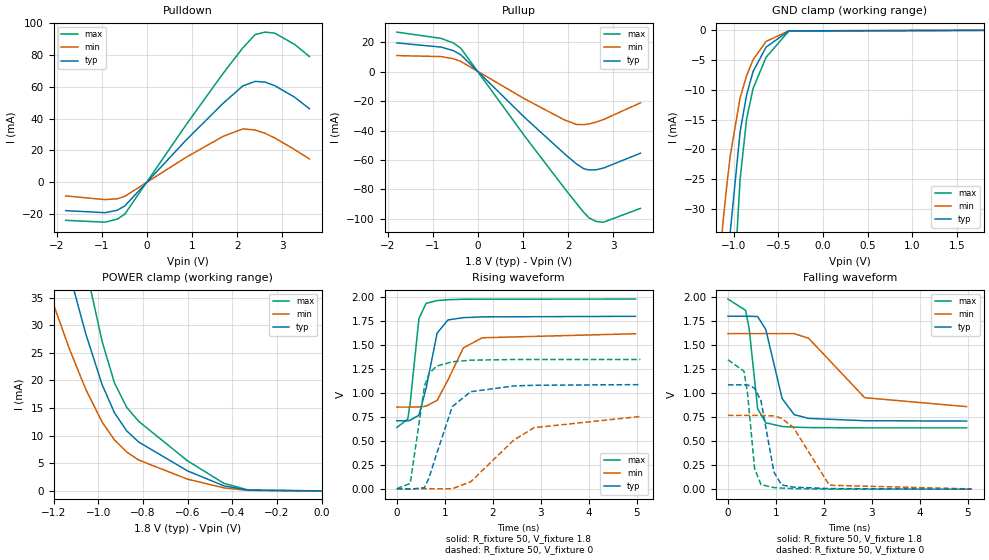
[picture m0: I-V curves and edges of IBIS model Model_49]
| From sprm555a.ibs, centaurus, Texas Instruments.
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| Model based on original model for BC1833DV40DCMLBPBFBP18LL_SSDHH
|   Sub model BC40DCM_H_PUPDOFF_10P_SC1_1P8
[model]   Model_49
|[Description]  [1.8V-I/O-PI-SLOW, IND, 10%]
|   Slow slew rate (SC1 = 1),Weak pull up/down disabled,Industrial
|   temperature range (-40C to 125C, 25C nominal),10% power supply
|   tolerance
|[Input Load]   PI
|[Output Drive] SLOW
|Voltage   1.8V
|Mode   I/O
Model_type   I/O
Polarity   Non-Inverting
Enable   Active-Low
Vinl =  0.63
Vinh =  1.17
Cref =  15pF
Rref =  100.0000M
Vref =  0V
Vmeas =  0.9
C_comp   2.344425p   2.25547p   2.363434p
[Model Spec]
Vinl   0.63   0.567   0.693
Vinh   1.17   1.053   1.287
[Temperature Range]   25   125   -40
[Voltage Range]   1.8   1.62   1.98
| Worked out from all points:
|   slope of the pulldown table from 0 to 0.27 V, typ, clamps not added: 32.2 ohm
|   slope of the pullup table from 0 to 0.27 V, typ, clamps not added: 32.6 ohm
|   GND clamp passes 1 mA (typ) near -0.53 V on its own axis
|   POWER clamp passes 1 mA (typ) near -0.44 V on its own axis
|   rising waveform, R_fixture 50, V_fixture 1.8: 20-80 % time 249ps typ, 424ps min, 162ps max; typ from 0.709 V to 1.8 V
|   rising waveform, R_fixture 50, V_fixture 0: 20-80 % time 430ps typ, 992ps min, 232ps max; typ from 0 V to 1.09 V
|   falling waveform, R_fixture 50, V_fixture 1.8: 20-80 % time 310ps typ, 792ps min, 166ps max; typ from 1.8 V to 0.709 V
|   falling waveform, R_fixture 50, V_fixture 0: 20-80 % time 228ps typ, 465ps min, 151ps max; typ from 1.09 V to 0 V
[POWER_clamp]
-1.8V     158.8mA    112.5mA    219.7mA
-1.255V   59.93mA    40mA       84.85mA
-1.127V   39.08mA    25.51mA    55.74mA
-1.055V   28.36mA    18.34mA    40.4mA
-981.8mV  19.18mA    12.43mA    26.97mA
-927.3mV  14.16mA    9.242mA    19.58mA
-872.7mV  10.89mA    7.052mA    15.14mA
-818.2mV  8.843mA    5.581mA    12.58mA
-600mV    3.63mA     2.129mA    5.448mA
-436.4mV  903.9uA    539.1uA    1.358mA
-327.3mV  138.2uA    94.86uA    160.4uA
0V        19.3nA     120.3nA    352.8nA
[Pulldown]
-1.8V     -17.92mA   -8.674mA   -24.03mA
-927.3mV  -19.22mA   -10.99mA   -25.2mA
-654.5mV  -17.65mA   -10.46mA   -23.22mA
-490.9mV  -14.97mA   -8.904mA   -20.12mA
872.7mV   26.63mA    15.72mA    36.29mA
1.691V    49.7mA     28.87mA    68.59mA
2.127V    60.63mA    33.53mA    84.59mA
2.4V      63.43mA    32.84mA    92.9mA
2.618V    62.99mA    30.74mA    94.47mA
2.836V    60.69mA    27.76mA    93.76mA
3.273V    53.49mA    20.53mA    86.73mA
3.6V      46.26mA    14.64mA    79.12mA
[Pullup]
-1.8V     19.42mA    10.82mA    26.76mA
-818.2mV  16.58mA    10.15mA    22.47mA
-545.5mV  14.19mA    8.648mA    19.37mA
-381.8mV  11.34mA    6.842mA    15.75mA
1.036V    -31.26mA   -18.6mA    -43.9mA
1.909V    -55.59mA   -32.73mA   -78.89mA
2.182V    -62.72mA   -35.92mA   -89.47mA
2.345V    -65.94mA   -36.05mA   -95.62mA
2.455V    -66.75mA   -35.58mA   -99.18mA
2.618V    -66.67mA   -34.29mA   -101.7mA
2.782V    -65.46mA   -32.56mA   -102.2mA
3.6V      -55.4mA    -21.22mA   -92.82mA
[GND_clamp]
-1.8V     -270.2mA   -170.2mA   -430.1mA
-1.255V   -91.66mA   -55.91mA   -148.4mA
-1.145V   -59.91mA   -36.44mA   -97.09mA
-1.109V   -50.48mA   -30.83mA   -81.55mA
-1.073V   -41.73mA   -25.65mA   -67.05mA
-1.036V   -33.66mA   -20.92mA   -53.59mA
-927.3mV  -17.07mA   -11.35mA   -25.04mA
-854.5mV  -10.86mA   -7.616mA   -14.91mA
-781.8mV  -6.919mA   -4.945mA   -9.771mA
-636.4mV  -2.823mA   -1.868mA   -4.529mA
-381.8mV  -84.73uA   -78.7uA    -126.1uA
1.8V      19.3nA     3.129uA    310.3nA
[Ramp]
dV/dt_f 0.66158729/0.31312099n 0.46775844/0.81509621n  0.8109244/0.168039n
dV/dt_r 0.65950887/0.43320351n 0.47445953/1.0525249n 0.81582639/0.23270059n
R_load = 50
[Rising Waveform]
R_fixture = 50
V_fixture = 1.8
V_fixture_min = 1.62
V_fixture_max = 1.98
0s        709.2mV    852.1mV    638.7mV
228.5ps   709.2mV    852.1mV    727.2mV
279ps     715mV      852.1mV    897.2mV
460.7ps   767.4mV    852.4mV    1.775V
609.6ps   1.047V     863.3mV    1.935V
840.4ps   1.625V     922.2mV    1.965V
1.066ns   1.762V     1.136V     1.973V
1.387ns   1.786V     1.471V     1.978V
1.781ns   1.794V     1.576V     1.979V
4.974ns   1.8V       1.618V     1.98V
[Rising Waveform]
R_fixture = 50
V_fixture = 0
V_fixture_min = 0
V_fixture_max = 0
0s        0V         0V         0V
279.1ps   -4.496mV   0V         55.36mV
575.6ps   11.17mV    0V         1.07V
671.5ps   114.3mV    0V         1.203V
828.7ps   363mV      0V         1.28V
1.155ns   856.5mV    0V         1.325V
1.537ns   1.013V     71.46mV    1.342V
2.437ns   1.073V     507.6mV    1.349V
2.86ns    1.08V      637.5mV    1.349V
5.077ns   1.087V     754.7mV    1.349V
[Falling Waveform]
R_fixture = 50
V_fixture = 1.8
V_fixture_min = 1.62
V_fixture_max = 1.98
0s        1.801V     1.62V      1.98V
369.4ps   1.801V     1.62V      1.862V
442.6ps   1.801V     1.62V      1.671V
619.8ps   1.798V     1.62V      837.6mV
788.4ps   1.664V     1.62V      691.6mV
1.13ns    943.7mV    1.62V      652.7mV
1.38ns    776mV      1.62V      645.7mV
1.681ns   737.2mV    1.572V     641.7mV
2.85ns    712.9mV    952.7mV    638.2mV
4.974ns   709mV      859.7mV    637.9mV
[Falling Waveform]
R_fixture = 50
V_fixture = 0
V_fixture_min = 0
V_fixture_max = 0
0s        1.086V     768.6mV    1.348V
334.1ps   1.086V     768.6mV    1.229V
410.6ps   1.086V     768.6mV    991.6mV
554.9ps   1.052V     768.6mV    217.6mV
688.5ps   921.5mV    768.6mV    47.07mV
958.6ps   178.4mV    762.8mV    16.84mV
1.117ns   44.46mV    738.1mV    11.67mV
1.36ns    21.32mV    645.9mV    5.206mV
2.114ns   6.036mV    40.95mV    0V
5.077ns   0V         2.212mV    0V
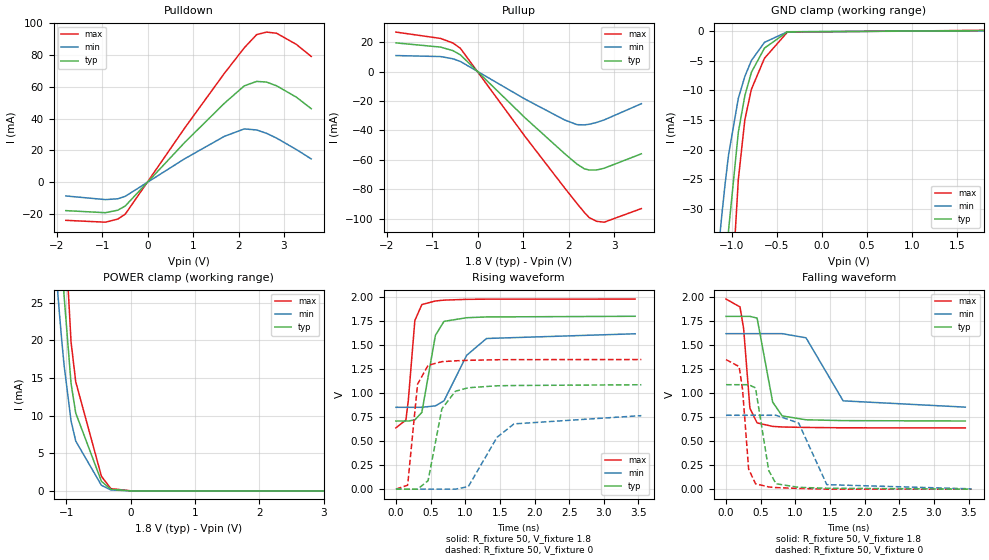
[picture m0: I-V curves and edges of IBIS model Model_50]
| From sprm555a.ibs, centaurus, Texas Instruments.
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| Model based on original model for BC1833DV40DCMLBPBFBP18LL_SSDHH
|   Sub model BC40DCM_H_PD_ON_10P_!SC1_1P8
[model]   Model_50
|[Description]  [1.8V-I/O-PD-FAST, IND, 10%]
|   Fast slew rate (SC1 = 0),Weak internal pull-down,Industrial
|   temperature range (-40C to 125C, 25C nominal),10% power supply
|   tolerance
|[Input Load]   PD
|[Output Drive] FAST
|Voltage   1.8V
|Mode   I/O
Model_type   I/O
Polarity   Non-Inverting
Enable   Active-Low
Vinl =  0.63
Vinh =  1.17
Cref =  15pF
Rref =  100.0000M
Vref =  0V
Vmeas =  0.9
C_comp   2.344425p   2.25547p   2.363434p
[Model Spec]
Vinl   0.63   0.567   0.693
Vinh   1.17   1.053   1.287
[Temperature Range]   25   125   -40
[Voltage Range]   1.8   1.62   1.98
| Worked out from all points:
|   slope of the pulldown table from 0 to 0.27 V, typ, clamps not added: 32.2 ohm
|   slope of the pullup table from 0 to 0.27 V, typ, clamps not added: 32.5 ohm
|   GND clamp passes 1 mA (typ) near -0.53 V on its own axis
|   POWER clamp passes 1 mA (typ) near -0.43 V on its own axis
|   rising waveform, R_fixture 50, V_fixture 1.8: 20-80 % time 145ps typ, 331ps min, 88.8ps max; typ from 0.708 V to 1.8 V
|   rising waveform, R_fixture 50, V_fixture 0: 20-80 % time 176ps typ, 381ps min, 101ps max; typ from 0 V to 1.09 V
|   falling waveform, R_fixture 50, V_fixture 1.8: 20-80 % time 130ps typ, 293ps min, 86ps max; typ from 1.8 V to 0.709 V
|   falling waveform, R_fixture 50, V_fixture 0: 20-80 % time 113ps typ, 213ps min, 82.8ps max; typ from 1.09 V to 0 V
[POWER_clamp]
-1.8V     158.9mA    112.6mA    219.9mA
-1.255V   60.04mA    40.04mA    85.04mA
-1.145V   41.99mA    27.45mA    59.9mA
-1.109V   36.4mA     23.66mA    51.96mA
-1.073V   31.03mA    20.08mA    44.3mA
-1.036V   25.91mA    16.71mA    36.9mA
-927.3mV  14.27mA    9.297mA    19.77mA
-854.5mV  10.33mA    6.619mA    14.49mA
-454.5mV  1.273mA    741.7uA    1.94mA
-309.1mV  221.6uA    132.8uA    307.9uA
18.18mV   0A         0A         0A
3.6V      0A         0A         0A
[Pulldown]
-1.8V     -17.92mA   -8.674mA   -24.03mA
-927.3mV  -19.22mA   -10.99mA   -25.2mA
-654.5mV  -17.65mA   -10.46mA   -23.22mA
-490.9mV  -14.97mA   -8.904mA   -20.12mA
818.2mV   25.05mA    14.78mA    34.16mA
1.691V    49.7mA     28.87mA    68.58mA
2.127V    60.63mA    33.53mA    84.59mA
2.4V      63.43mA    32.85mA    92.9mA
2.618V    62.99mA    30.74mA    94.47mA
2.836V    60.69mA    27.76mA    93.76mA
3.273V    53.49mA    20.53mA    86.73mA
3.6V      46.26mA    14.64mA    79.12mA
[Pullup]
-1.8V     19.47mA    10.86mA    26.81mA
-818.2mV  16.61mA    10.18mA    22.5mA
-545.5mV  14.2mA     8.665mA    19.39mA
-381.8mV  11.35mA    6.855mA    15.77mA
1.036V    -31.31mA   -18.66mA   -43.94mA
1.909V    -55.72mA   -32.86mA   -78.99mA
2.182V    -62.87mA   -36.1mA    -89.59mA
2.345V    -66.12mA   -36.26mA   -95.76mA
2.455V    -66.95mA   -35.82mA   -99.33mA
2.618V    -66.9mA    -34.58mA   -101.8mA
2.782V    -65.72mA   -32.89mA   -102.4mA
3.6V      -55.92mA   -21.86mA   -93.15mA
[GND_clamp]
-1.8V     -270.2mA   -170.2mA   -430.1mA
-1.255V   -91.66mA   -55.91mA   -148.4mA
-1.145V   -59.91mA   -36.45mA   -97.1mA
-1.109V   -50.48mA   -30.83mA   -81.56mA
-1.073V   -41.73mA   -25.65mA   -67.06mA
-1.036V   -33.67mA   -20.93mA   -53.6mA
-927.3mV  -17.08mA   -11.35mA   -25.06mA
-854.5mV  -10.88mA   -7.623mA   -14.95mA
-781.8mV  -6.944mA   -4.955mA   -9.81mA
-636.4mV  -2.852mA   -1.883mA   -4.568mA
-381.8mV  -107.5uA   -91.83uA   -158.4uA
1.8V      101.9uA    59.86uA    152.6uA
[Ramp]
dV/dt_f 0.66466633/0.13254164n 0.47017584/0.29934086n 0.81362785/87.565615p
dV/dt_r   0.663957/0.17824598n  0.4809099/0.3977937n  0.8179783/0.10140493n
R_load = 50
[Rising Waveform]
R_fixture = 50
V_fixture = 1.8
V_fixture_min = 1.62
V_fixture_max = 1.98
0s        708.5mV    851.3mV    637.7mV
143.7ps   708.5mV    851.3mV    718.9mV
178.5ps   708.5mV    851.3mV    921.1mV
273.2ps   720.3mV    851.3mV    1.754V
374.1ps   798mV      851.3mV    1.92V
569.9ps   1.6V       866.3mV    1.957V
694.1ps   1.745V     919.3mV    1.966V
1.021ns   1.783V     1.392V     1.974V
1.307ns   1.791V     1.567V     1.976V
3.453ns   1.798V     1.616V     1.977V
[Rising Waveform]
R_fixture = 50
V_fixture = 0
V_fixture_min = 0
V_fixture_max = 0
0s        0V         0V         0V
168.9ps   0V         0V         40.84mV
312.3ps   0V         0V         1.092V
464.1ps   88.01mV    0V         1.288V
663.2ps   835.8mV    0V         1.326V
857.8ps   1.018V     0V         1.335V
1.045ns   1.055V     26.66mV    1.34V
1.459ns   1.075V     539.2mV    1.346V
1.704ns   1.078V     679mV      1.347V
3.542ns   1.086V     764.7mV    1.348V
[Falling Waveform]
R_fixture = 50
V_fixture = 1.8
V_fixture_min = 1.62
V_fixture_max = 1.98
0s        1.798V     1.618V     1.978V
201.6ps   1.798V     1.618V     1.896V
253.7ps   1.798V     1.618V     1.671V
344.4ps   1.798V     1.618V     841.4mV
448.2ps   1.78V      1.618V     689.6mV
672.7ps   906.5mV    1.618V     653mV
809.7ps   762.1mV    1.618V     647.1mV
1.154ns   721.9mV    1.575V     642.3mV
1.69ns    713.1mV    918.9mV    638.4mV
3.453ns   709.3mV    853.5mV    637.1mV
[Falling Waveform]
R_fixture = 50
V_fixture = 0
V_fixture_min = 0
V_fixture_max = 0
0s        1.087V     768.9mV    1.348V
189.2ps   1.087V     768.9mV    1.275V
238.1ps   1.087V     768.9mV    1.038V
325.8ps   1.087V     768.9mV    209.8mV
425.1ps   1.054V     768.9mV    56.16mV
615.9ps   194.4mV    768.9mV    22.91mV
720.9ps   56.52mV    768.9mV    16.38mV
1.048ns   18.77mV    687.9mV    7.302mV
1.454ns   9.815mV    46.84mV    0V
3.542ns   0V         3.333mV    0V
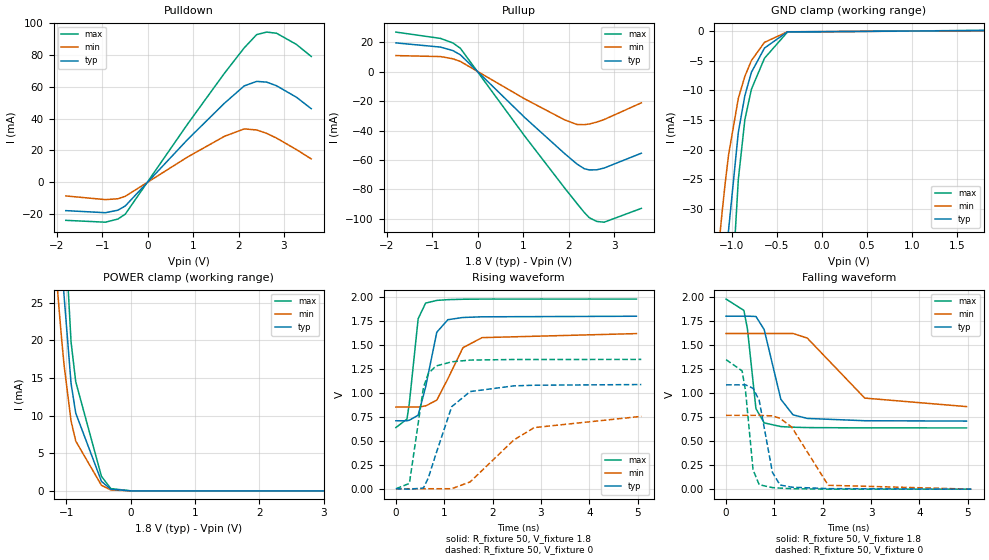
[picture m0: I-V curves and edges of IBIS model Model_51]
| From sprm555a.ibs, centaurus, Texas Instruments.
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| Model based on original model for BC1833DV40DCMLBPBFBP18LL_SSDHH
|   Sub model BC40DCM_H_PD_ON_10P_SC1_1P8
[model]   Model_51
|[Description]  [1.8V-I/O-PD-SLOW, IND, 10%]
|   Slow slew rate (SC1 = 1),Weak internal pull-down,Industrial
|   temperature range (-40C to 125C, 25C nominal),10% power supply
|   tolerance
|[Input Load]   PD
|[Output Drive] SLOW
|Voltage   1.8V
|Mode   I/O
Model_type   I/O
Polarity   Non-Inverting
Enable   Active-Low
Vinl =  0.63
Vinh =  1.17
Cref =  15pF
Rref =  100.0000M
Vref =  0V
Vmeas =  0.9
C_comp   2.344425p   2.25547p   2.363434p
[Model Spec]
Vinl   0.63   0.567   0.693
Vinh   1.17   1.053   1.287
[Temperature Range]   25   125   -40
[Voltage Range]   1.8   1.62   1.98
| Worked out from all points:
|   slope of the pulldown table from 0 to 0.27 V, typ, clamps not added: 32.2 ohm
|   slope of the pullup table from 0 to 0.27 V, typ, clamps not added: 32.6 ohm
|   GND clamp passes 1 mA (typ) near -0.53 V on its own axis
|   POWER clamp passes 1 mA (typ) near -0.43 V on its own axis
|   rising waveform, R_fixture 50, V_fixture 1.8: 20-80 % time 249ps typ, 424ps min, 162ps max; typ from 0.708 V to 1.8 V
|   rising waveform, R_fixture 50, V_fixture 0: 20-80 % time 429ps typ, 992ps min, 231ps max; typ from 0 V to 1.09 V
|   falling waveform, R_fixture 50, V_fixture 1.8: 20-80 % time 310ps typ, 792ps min, 166ps max; typ from 1.8 V to 0.708 V
|   falling waveform, R_fixture 50, V_fixture 0: 20-80 % time 227ps typ, 466ps min, 151ps max; typ from 1.08 V to 0 V
[POWER_clamp]
-1.8V     158.9mA    112.6mA    219.9mA
-1.255V   60.04mA    40.04mA    85.04mA
-1.145V   41.99mA    27.45mA    59.9mA
-1.109V   36.4mA     23.66mA    51.96mA
-1.073V   31.03mA    20.08mA    44.3mA
-1.036V   25.91mA    16.71mA    36.9mA
-927.3mV  14.27mA    9.297mA    19.77mA
-854.5mV  10.33mA    6.619mA    14.49mA
-454.5mV  1.273mA    741.7uA    1.94mA
-309.1mV  221.6uA    132.8uA    307.9uA
18.18mV   0A         0A         0A
3.6V      0A         0A         0A
[Pulldown]
-1.8V     -17.92mA   -8.674mA   -24.03mA
-927.3mV  -19.22mA   -10.99mA   -25.2mA
-654.5mV  -17.65mA   -10.46mA   -23.22mA
-490.9mV  -14.97mA   -8.904mA   -20.12mA
872.7mV   26.63mA    15.72mA    36.29mA
1.691V    49.7mA     28.87mA    68.58mA
2.127V    60.63mA    33.53mA    84.59mA
2.4V      63.43mA    32.85mA    92.9mA
2.618V    62.99mA    30.74mA    94.47mA
2.836V    60.69mA    27.76mA    93.76mA
3.273V    53.49mA    20.53mA    86.73mA
3.6V      46.26mA    14.64mA    79.12mA
[Pullup]
-1.8V     19.42mA    10.82mA    26.76mA
-818.2mV  16.58mA    10.15mA    22.47mA
-545.5mV  14.19mA    8.648mA    19.37mA
-381.8mV  11.34mA    6.842mA    15.75mA
1.036V    -31.26mA   -18.6mA    -43.9mA
1.909V    -55.59mA   -32.73mA   -78.89mA
2.182V    -62.71mA   -35.92mA   -89.46mA
2.345V    -65.94mA   -36.05mA   -95.62mA
2.455V    -66.75mA   -35.58mA   -99.18mA
2.618V    -66.67mA   -34.29mA   -101.7mA
2.782V    -65.46mA   -32.56mA   -102.2mA
3.6V      -55.4mA    -21.22mA   -92.82mA
[GND_clamp]
-1.8V     -270.2mA   -170.2mA   -430.1mA
-1.255V   -91.66mA   -55.91mA   -148.4mA
-1.145V   -59.91mA   -36.45mA   -97.1mA
-1.109V   -50.48mA   -30.83mA   -81.56mA
-1.073V   -41.73mA   -25.65mA   -67.06mA
-1.036V   -33.67mA   -20.93mA   -53.6mA
-927.3mV  -17.08mA   -11.35mA   -25.06mA
-854.5mV  -10.88mA   -7.623mA   -14.95mA
-781.8mV  -6.944mA   -4.955mA   -9.81mA
-636.4mV  -2.852mA   -1.883mA   -4.568mA
-381.8mV  -107.5uA   -91.83uA   -158.4uA
1.8V      101.9uA    59.86uA    152.6uA
[Ramp]
dV/dt_f 0.66084939/0.31244976n 0.46735303/0.81433888n  0.8098709/0.16773637n
dV/dt_r 0.65873585/0.43257283n 0.47403165/1.0514155n 0.81471047/0.23229215n
R_load = 50
[Rising Waveform]
R_fixture = 50
V_fixture = 1.8
V_fixture_min = 1.62
V_fixture_max = 1.98
0s        708.4mV    851.3mV    637.9mV
227.9ps   708.4mV    851.3mV    726mV
275.2ps   713.7mV    851.3mV    881.4mV
460.1ps   766.4mV    851.6mV    1.773V
614.7ps   1.062V     863.3mV    1.935V
845.1ps   1.631V     923.8mV    1.963V
1.074ns   1.762V     1.146V     1.971V
1.386ns   1.785V     1.47V      1.975V
1.781ns   1.792V     1.575V     1.977V
4.974ns   1.798V     1.617V     1.977V
[Rising Waveform]
R_fixture = 50
V_fixture = 0
V_fixture_min = 0
V_fixture_max = 0
0s        0V         0V         0V
278.5ps   -4.495mV   0V         55.36mV
569.3ps   7.749mV    0V         1.057V
671ps     114.4mV    0V         1.203V
828.2ps   363.1mV    0V         1.279V
1.154ns   855.4mV    0V         1.323V
1.536ns   1.013V     71.36mV    1.341V
2.436ns   1.072V     507.4mV    1.347V
2.86ns    1.079V     637.3mV    1.347V
5.076ns   1.086V     754.3mV    1.348V
[Falling Waveform]
R_fixture = 50
V_fixture = 1.8
V_fixture_min = 1.62
V_fixture_max = 1.98
0s        1.799V     1.619V     1.977V
368.9ps   1.799V     1.619V     1.859V
442.2ps   1.799V     1.619V     1.667V
618ps     1.796V     1.619V     837.7mV
788.4ps   1.66V      1.619V     689.3mV
1.133ns   934.9mV    1.619V     651.1mV
1.385ns   773mV      1.619V     644.3mV
1.68ns    735.7mV    1.571V     640.5mV
2.868ns   711.7mV    947.2mV    637.2mV
4.974ns   708.1mV    858.7mV    637mV
[Falling Waveform]
R_fixture = 50
V_fixture = 0
V_fixture_min = 0
V_fixture_max = 0
0s        1.085V     767.8mV    1.347V
332.1ps   1.085V     767.8mV    1.23V
404.3ps   1.085V     767.8mV    1.016V
558.5ps   1.049V     767.8mV    201.7mV
685.2ps   924.8mV    767.8mV    46.5mV
959.4ps   174mV      761.9mV    15.99mV
1.117ns   43.41mV    737.3mV    11.07mV
1.359ns   20.58mV    645mV      4.808mV
2.113ns   5.595mV    40.31mV    0V
5.076ns   0V         0V         0V
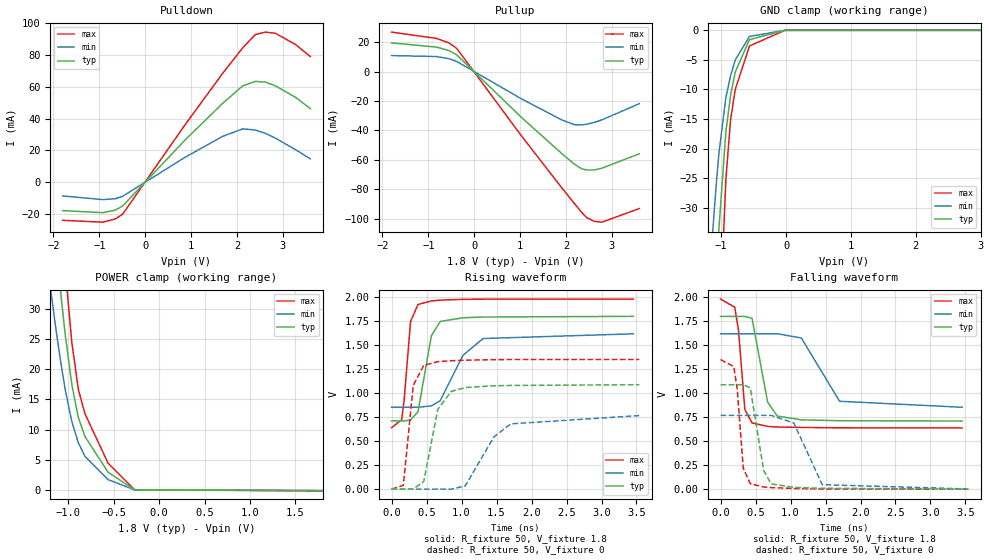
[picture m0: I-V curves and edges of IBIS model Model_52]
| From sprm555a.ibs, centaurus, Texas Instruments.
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| Model based on original model for BC1833DV40DCMLBPBFBP18LL_SSDHH
|   Sub model BC40DCM_H_PU_ON_10P_!SC1_1P8
[model]   Model_52
|[Description]  [1.8V-I/O-PU-FAST, IND, 10%]
|   Fast slew rate (SC1 = 0),Weak internal pull-up,Industrial
|   temperature range (-40C to 125C, 25C nominal),10% power supply
|   tolerance
|[Input Load]   PU
|[Output Drive] FAST
|Voltage   1.8V
|Mode   I/O
Model_type   I/O
Polarity   Non-Inverting
Enable   Active-Low
Vinl =  0.63
Vinh =  1.17
Cref =  15pF
Rref =  100.0000M
Vref =  0V
Vmeas =  0.9
C_comp   2.344425p   2.25547p   2.363434p
[Model Spec]
Vinl   0.63   0.567   0.693
Vinh   1.17   1.053   1.287
[Temperature Range]   25   125   -40
[Voltage Range]   1.8   1.62   1.98
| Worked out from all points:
|   slope of the pulldown table from 0 to 0.27 V, typ, clamps not added: 32.2 ohm
|   slope of the pullup table from 0 to 0.27 V, typ, clamps not added: 32.5 ohm
|   GND clamp passes 1 mA (typ) near -0.52 V on its own axis
|   POWER clamp passes 1 mA (typ) near -0.44 V on its own axis
|   rising waveform, R_fixture 50, V_fixture 1.8: 20-80 % time 145ps typ, 330ps min, 88.8ps max; typ from 0.711 V to 1.8 V
|   rising waveform, R_fixture 50, V_fixture 0: 20-80 % time 176ps typ, 382ps min, 101ps max; typ from 0.002 V to 1.09 V
|   falling waveform, R_fixture 50, V_fixture 1.8: 20-80 % time 130ps typ, 293ps min, 86ps max; typ from 1.8 V to 0.711 V
|   falling waveform, R_fixture 50, V_fixture 0: 20-80 % time 113ps typ, 213ps min, 82.8ps max; typ from 1.09 V to 0.002 V
[POWER_clamp]
-1.8V     158.8mA    112.5mA    219.8mA
-1.255V   59.97mA    40.01mA    84.9mA
-1.145V   41.92mA    27.42mA    59.75mA
-1.109V   36.32mA    23.63mA    51.82mA
-1.073V   30.96mA    20.05mA    44.15mA
-1.036V   25.83mA    16.67mA    36.75mA
-963.6mV  17.54mA    11.39mA    24.55mA
-890.9mV  12.01mA    7.801mA    16.66mA
-818.2mV  8.875mA    5.6mA      12.63mA
-563.6mV  2.954mA    1.727mA    4.458mA
-272.7mV  55.97uA    39.41uA    57.82uA
1.8V      -99.94uA   -59.68uA   -146.8uA
[Pulldown]
-1.8V     -17.92mA   -8.674mA   -24.03mA
-927.3mV  -19.22mA   -10.99mA   -25.21mA
-654.5mV  -17.65mA   -10.46mA   -23.22mA
-490.9mV  -14.97mA   -8.904mA   -20.12mA
872.7mV   26.63mA    15.72mA    36.29mA
1.691V    49.7mA     28.87mA    68.59mA
2.127V    60.63mA    33.53mA    84.59mA
2.4V      63.43mA    32.84mA    92.9mA
2.618V    62.99mA    30.74mA    94.47mA
2.836V    60.69mA    27.76mA    93.76mA
3.273V    53.49mA    20.53mA    86.73mA
3.6V      46.26mA    14.64mA    79.11mA
[Pullup]
-1.8V     19.47mA    10.86mA    26.81mA
-818.2mV  16.61mA    10.18mA    22.5mA
-545.5mV  14.21mA    8.665mA    19.39mA
-381.8mV  11.35mA    6.855mA    15.77mA
1.036V    -31.31mA   -18.66mA   -43.94mA
1.909V    -55.72mA   -32.86mA   -78.99mA
2.182V    -62.87mA   -36.1mA    -89.59mA
2.345V    -66.12mA   -36.26mA   -95.76mA
2.455V    -66.95mA   -35.82mA   -99.33mA
2.618V    -66.9mA    -34.58mA   -101.8mA
2.782V    -65.73mA   -32.89mA   -102.4mA
3.6V      -55.92mA   -21.86mA   -93.15mA
[GND_clamp]
-1.8V     -270.2mA   -170.2mA   -430.1mA
-1.255V   -91.68mA   -55.92mA   -148.5mA
-1.145V   -59.94mA   -36.46mA   -97.15mA
-1.109V   -50.51mA   -30.84mA   -81.62mA
-1.073V   -41.77mA   -25.67mA   -67.14mA
-1.036V   -33.71mA   -20.94mA   -53.69mA
-927.3mV  -17.15mA   -11.38mA   -25.2mA
-854.5mV  -10.96mA   -7.657mA   -15.09mA
-781.8mV  -7.031mA   -4.995mA   -9.958mA
-563.6mV  -1.569mA   -1.036mA   -2.651mA
-18.18mV  0A         0A         0A
3.6V      0A         0A         0A
[Ramp]
dV/dt_f 0.66463764/0.13263058n 0.47013209/0.29941611n 0.81359696/87.584176p
dV/dt_r 0.66384338/0.17819323n  0.4805998/0.39765783n  0.8179891/0.10135865n
R_load = 50
[Rising Waveform]
R_fixture = 50
V_fixture = 1.8
V_fixture_min = 1.62
V_fixture_max = 1.98
0s        710.6mV    852.8mV    640.5mV
143.7ps   710.6mV    852.8mV    722.2mV
178.5ps   710.6mV    852.8mV    925mV
270.8ps   721.7mV    852.8mV    1.745V
377.3ps   806.8mV    852.8mV    1.924V
567.9ps   1.597V     867.4mV    1.96V
694.7ps   1.747V     921.4mV    1.969V
1.021ns   1.785V     1.395V     1.977V
1.307ns   1.793V     1.569V     1.979V
3.453ns   1.8V       1.618V     1.98V
[Rising Waveform]
R_fixture = 50
V_fixture = 0
V_fixture_min = 0
V_fixture_max = 0
0s        2.403mV    0V         0V
167.8ps   2.403mV    0V         40.79mV
309.1ps   2.403mV    0V         1.082V
459.2ps   77.71mV    0V         1.289V
660.4ps   831.9mV    0V         1.328V
851.7ps   1.018V     0V         1.338V
1.053ns   1.058V     34.68mV    1.343V
1.461ns   1.077V     543.1mV    1.349V
1.702ns   1.08V      680.1mV    1.35V
3.54ns    1.088V     766.2mV    1.351V
[Falling Waveform]
R_fixture = 50
V_fixture = 1.8
V_fixture_min = 1.62
V_fixture_max = 1.98
0s        1.8V       1.62V      1.981V
202.5ps   1.8V       1.62V      1.896V
255.7ps   1.8V       1.62V      1.659V
347ps     1.8V       1.62V      831.6mV
449.8ps   1.78V      1.62V      691.6mV
673.3ps   907.4mV    1.62V      655.6mV
810.6ps   763.8mV    1.62V      649.7mV
1.154ns   723.8mV    1.576V     644.9mV
1.701ns   715.1mV    917.3mV    641mV
3.453ns   711.4mV    854.9mV    639.8mV
[Falling Waveform]
R_fixture = 50
V_fixture = 0
V_fixture_min = 0
V_fixture_max = 0
0s        1.089V     770.8mV    1.351V
189.2ps   1.089V     770.8mV    1.278V
238.1ps   1.089V     770.8mV    1.041V
324.3ps   1.089V     770.8mV    220mV
425.1ps   1.056V     770.8mV    58.76mV
616.3ps   195.4mV    770.8mV    25.42mV
722.1ps   58.16mV    770.8mV    18.85mV
1.048ns   20.72mV    689.9mV    9.786mV
1.453ns   11.74mV    49.09mV    4.325mV
3.54ns    2.495mV    4.926mV    2.572mV
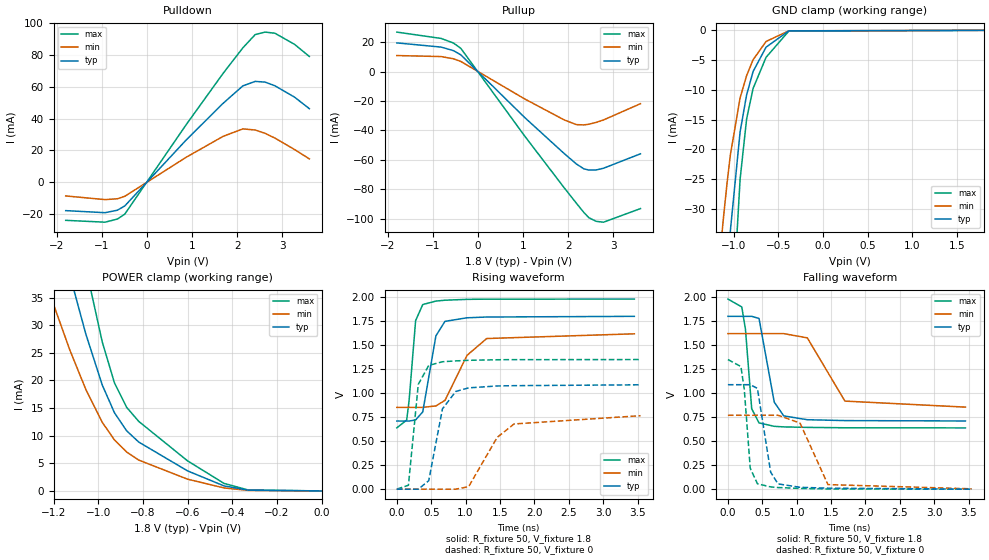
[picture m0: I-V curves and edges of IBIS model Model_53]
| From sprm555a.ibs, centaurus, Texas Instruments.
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| Model based on original model for BC1833DV40DCMLBPBFBP18LL_SSDHH
|   Sub model BC40DCM_H_PUPDOFF_10P_!SC1_1P8
[model]   Model_53
|[Description]  [1.8V-I/O-PI-FAST, IND, 10%]
|   Fast slew rate (SC1 = 0),Weak pull up/down disabled,Industrial
|   temperature range (-40C to 125C, 25C nominal),10% power supply
|   tolerance
|[Input Load]   PI
|[Output Drive] FAST
|Voltage   1.8V
|Mode   I/O
Model_type   I/O
Polarity   Non-Inverting
Enable   Active-Low
Vinl =  0.63
Vinh =  1.17
Cref =  15pF
Rref =  100.0000M
Vref =  0V
Vmeas =  0.9
C_comp   2.344425p   2.25547p   2.363434p
[Model Spec]
Vinl   0.63   0.567   0.693
Vinh   1.17   1.053   1.287
[Temperature Range]   25   125   -40
[Voltage Range]   1.8   1.62   1.98
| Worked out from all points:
|   slope of the pulldown table from 0 to 0.27 V, typ, clamps not added: 32.2 ohm
|   slope of the pullup table from 0 to 0.27 V, typ, clamps not added: 32.5 ohm
|   GND clamp passes 1 mA (typ) near -0.53 V on its own axis
|   POWER clamp passes 1 mA (typ) near -0.44 V on its own axis
|   rising waveform, R_fixture 50, V_fixture 1.8: 20-80 % time 145ps typ, 331ps min, 89ps max; typ from 0.709 V to 1.8 V
|   rising waveform, R_fixture 50, V_fixture 0: 20-80 % time 176ps typ, 382ps min, 101ps max; typ from 0 V to 1.09 V
|   falling waveform, R_fixture 50, V_fixture 1.8: 20-80 % time 130ps typ, 293ps min, 86.1ps max; typ from 1.8 V to 0.71 V
|   falling waveform, R_fixture 50, V_fixture 0: 20-80 % time 113ps typ, 213ps min, 83ps max; typ from 1.09 V to 0 V
[POWER_clamp]
-1.8V     158.8mA    112.5mA    219.7mA
-1.255V   59.93mA    40mA       84.85mA
-1.127V   39.08mA    25.51mA    55.74mA
-1.055V   28.36mA    18.34mA    40.4mA
-981.8mV  19.18mA    12.43mA    26.97mA
-927.3mV  14.16mA    9.242mA    19.58mA
-872.7mV  10.89mA    7.052mA    15.14mA
-818.2mV  8.843mA    5.581mA    12.58mA
-600mV    3.63mA     2.129mA    5.448mA
-436.4mV  903.9uA    539.1uA    1.358mA
-327.3mV  138.2uA    94.86uA    160.4uA
0V        19.3nA     120.3nA    352.8nA
[Pulldown]
-1.8V     -17.92mA   -8.674mA   -24.03mA
-927.3mV  -19.22mA   -10.99mA   -25.2mA
-654.5mV  -17.65mA   -10.46mA   -23.22mA
-490.9mV  -14.97mA   -8.904mA   -20.12mA
872.7mV   26.63mA    15.72mA    36.29mA
1.691V    49.7mA     28.87mA    68.59mA
2.127V    60.63mA    33.53mA    84.59mA
2.4V      63.43mA    32.84mA    92.9mA
2.618V    62.99mA    30.74mA    94.47mA
2.836V    60.69mA    27.76mA    93.76mA
3.273V    53.49mA    20.53mA    86.73mA
3.6V      46.26mA    14.64mA    79.11mA
[Pullup]
-1.8V     19.47mA    10.86mA    26.81mA
-818.2mV  16.61mA    10.18mA    22.5mA
-545.5mV  14.21mA    8.665mA    19.39mA
-381.8mV  11.35mA    6.855mA    15.77mA
1.036V    -31.31mA   -18.66mA   -43.94mA
1.909V    -55.72mA   -32.86mA   -78.99mA
2.182V    -62.87mA   -36.1mA    -89.59mA
2.345V    -66.12mA   -36.26mA   -95.76mA
2.455V    -66.95mA   -35.82mA   -99.33mA
2.618V    -66.9mA    -34.58mA   -101.8mA
2.782V    -65.72mA   -32.89mA   -102.4mA
3.6V      -55.92mA   -21.86mA   -93.15mA
[GND_clamp]
-1.8V     -270.2mA   -170.2mA   -430.1mA
-1.255V   -91.66mA   -55.91mA   -148.4mA
-1.145V   -59.91mA   -36.44mA   -97.09mA
-1.109V   -50.48mA   -30.83mA   -81.55mA
-1.073V   -41.73mA   -25.65mA   -67.05mA
-1.036V   -33.66mA   -20.92mA   -53.59mA
-927.3mV  -17.07mA   -11.35mA   -25.04mA
-854.5mV  -10.86mA   -7.616mA   -14.91mA
-781.8mV  -6.919mA   -4.945mA   -9.771mA
-636.4mV  -2.823mA   -1.868mA   -4.529mA
-381.8mV  -84.73uA   -78.7uA    -126.1uA
1.8V      19.3nA     3.129uA    310.3nA
[Ramp]
dV/dt_f 0.66538065/0.1328444n 0.47054654/0.29979879n 0.81467197/87.702019p
dV/dt_r 0.66473017/0.17860135n 0.48133748/0.39836838n 0.81909398/0.10165389n
R_load = 50
[Rising Waveform]
R_fixture = 50
V_fixture = 1.8
V_fixture_min = 1.62
V_fixture_max = 1.98
0s        709.3mV    852.1mV    638.7mV
143.7ps   709.3mV    852.1mV    720mV
178.5ps   709.3mV    852.1mV    922.4mV
273.4ps   721.2mV    852.1mV    1.756V
377.3ps   805.1mV    852.1mV    1.923V
568.3ps   1.597V     866.8mV    1.959V
700.5ps   1.748V     925.1mV    1.968V
1.021ns   1.785V     1.394V     1.977V
1.307ns   1.793V     1.569V     1.979V
3.453ns   1.8V       1.618V     1.98V
[Rising Waveform]
R_fixture = 50
V_fixture = 0
V_fixture_min = 0
V_fixture_max = 0
0s        0V         0V         0V
168.9ps   0V         0V         40.84mV
312.3ps   0V         0V         1.092V
464.2ps   88.18mV    0V         1.289V
663.2ps   836mV      0V         1.327V
857.7ps   1.018V     0V         1.336V
1.044ns   1.055V     25.73mV    1.342V
1.459ns   1.075V     539.2mV    1.348V
1.704ns   1.078V     679.1mV    1.349V
3.542ns   1.087V     765.1mV    1.35V
[Falling Waveform]
R_fixture = 50
V_fixture = 1.8
V_fixture_min = 1.62
V_fixture_max = 1.98
0s        1.8V       1.62V      1.98V
201.9ps   1.8V       1.62V      1.898V
255ps     1.8V       1.62V      1.665V
345.7ps   1.8V       1.62V      837.9mV
452.1ps   1.778V     1.62V      690.3mV
673.3ps   907.1mV    1.62V      654.7mV
810.7ps   763.5mV    1.62V      648.6mV
1.154ns   723.3mV    1.576V     643.5mV
1.701ns   714.3mV    917.2mV    639.4mV
3.453ns   710.3mV    854.5mV    638mV
[Falling Waveform]
R_fixture = 50
V_fixture = 0
V_fixture_min = 0
V_fixture_max = 0
0s        1.088V     769.7mV    1.35V
189.2ps   1.088V     769.7mV    1.277V
238.1ps   1.088V     769.7mV    1.04V
324.4ps   1.088V     769.7mV    218.8mV
428.9ps   1.05V      769.7mV    56.11mV
621.4ps   177.3mV    769.7mV    23.46mV
728.6ps   54.95mV    769.7mV    16.85mV
1.048ns   19.49mV    688.7mV    7.77mV
1.454ns   10.36mV    47.53mV    2.044mV
3.542ns   0V         3.732mV    0V
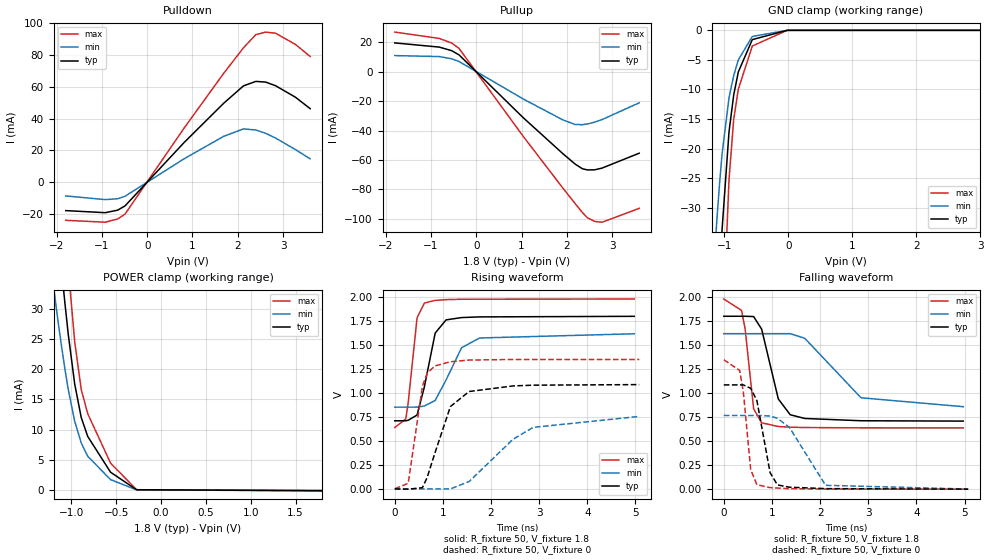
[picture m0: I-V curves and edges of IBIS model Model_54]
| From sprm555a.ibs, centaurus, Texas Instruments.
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| Model based on original model for BC1833DV40DCMLBPBFBP18LL_SSDHH
|   Sub model BC40DCM_H_PU_ON_10P_SC1_1P8
[model]   Model_54
|[Description]  [1.8V-I/O-PU-SLOW, IND, 10%]
|   Slow slew rate (SC1 = 1),Weak internal pull-up,Industrial
|   temperature range (-40C to 125C, 25C nominal),10% power supply
|   tolerance
|[Input Load]   PU
|[Output Drive] SLOW
|Voltage   1.8V
|Mode   I/O
Model_type   I/O
Polarity   Non-Inverting
Enable   Active-Low
Vinl =  0.63
Vinh =  1.17
Cref =  15pF
Rref =  100.0000M
Vref =  0V
Vmeas =  0.9
C_comp   2.344425p   2.25547p   2.363434p
[Model Spec]
Vinl   0.63   0.567   0.693
Vinh   1.17   1.053   1.287
[Temperature Range]   25   125   -40
[Voltage Range]   1.8   1.62   1.98
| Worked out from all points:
|   slope of the pulldown table from 0 to 0.27 V, typ, clamps not added: 32.2 ohm
|   slope of the pullup table from 0 to 0.27 V, typ, clamps not added: 32.6 ohm
|   GND clamp passes 1 mA (typ) near -0.52 V on its own axis
|   POWER clamp passes 1 mA (typ) near -0.44 V on its own axis
|   rising waveform, R_fixture 50, V_fixture 1.8: 20-80 % time 249ps typ, 423ps min, 162ps max; typ from 0.71 V to 1.8 V
|   rising waveform, R_fixture 50, V_fixture 0: 20-80 % time 430ps typ, 994ps min, 231ps max; typ from 0 V to 1.09 V
|   falling waveform, R_fixture 50, V_fixture 1.8: 20-80 % time 310ps typ, 792ps min, 166ps max; typ from 1.8 V to 0.71 V
|   falling waveform, R_fixture 50, V_fixture 0: 20-80 % time 228ps typ, 466ps min, 151ps max; typ from 1.09 V to 0.002 V
[POWER_clamp]
-1.8V     158.8mA    112.5mA    219.8mA
-1.255V   59.97mA    40.01mA    84.9mA
-1.145V   41.92mA    27.42mA    59.75mA
-1.109V   36.32mA    23.63mA    51.82mA
-1.073V   30.96mA    20.05mA    44.15mA
-1.036V   25.83mA    16.67mA    36.75mA
-963.6mV  17.54mA    11.39mA    24.55mA
-890.9mV  12.01mA    7.801mA    16.66mA
-818.2mV  8.875mA    5.6mA      12.63mA
-563.6mV  2.954mA    1.727mA    4.458mA
-272.7mV  55.97uA    39.41uA    57.82uA
1.8V      -99.94uA   -59.68uA   -146.8uA
[Pulldown]
-1.8V     -17.92mA   -8.674mA   -24.03mA
-927.3mV  -19.22mA   -10.99mA   -25.21mA
-654.5mV  -17.65mA   -10.46mA   -23.22mA
-490.9mV  -14.97mA   -8.904mA   -20.12mA
818.2mV   25.06mA    14.78mA    34.16mA
1.691V    49.7mA     28.87mA    68.59mA
2.127V    60.63mA    33.53mA    84.59mA
2.4V      63.43mA    32.84mA    92.9mA
2.618V    62.99mA    30.74mA    94.47mA
2.836V    60.69mA    27.76mA    93.76mA
3.273V    53.49mA    20.53mA    86.73mA
3.6V      46.26mA    14.64mA    79.12mA
[Pullup]
-1.8V     19.42mA    10.82mA    26.76mA
-818.2mV  16.58mA    10.15mA    22.47mA
-545.5mV  14.19mA    8.648mA    19.37mA
-381.8mV  11.34mA    6.842mA    15.75mA
1.036V    -31.26mA   -18.6mA    -43.9mA
1.909V    -55.59mA   -32.73mA   -78.89mA
2.182V    -62.71mA   -35.92mA   -89.46mA
2.345V    -65.94mA   -36.05mA   -95.62mA
2.455V    -66.75mA   -35.58mA   -99.18mA
2.618V    -66.67mA   -34.29mA   -101.7mA
2.782V    -65.47mA   -32.56mA   -102.2mA
3.6V      -55.4mA    -21.22mA   -92.82mA
[GND_clamp]
-1.8V     -270.2mA   -170.2mA   -430.1mA
-1.255V   -91.68mA   -55.92mA   -148.5mA
-1.145V   -59.94mA   -36.46mA   -97.15mA
-1.109V   -50.51mA   -30.84mA   -81.62mA
-1.073V   -41.77mA   -25.67mA   -67.14mA
-1.036V   -33.71mA   -20.94mA   -53.69mA
-927.3mV  -17.15mA   -11.38mA   -25.2mA
-854.5mV  -10.96mA   -7.657mA   -15.09mA
-781.8mV  -7.031mA   -4.995mA   -9.958mA
-563.6mV  -1.569mA   -1.036mA   -2.651mA
-18.18mV  0A         0A         0A
3.6V      0A         0A         0A
[Ramp]
dV/dt_f 0.66084473/0.31270442n 0.46734423/0.81439417n 0.80984764/0.16782911n
dV/dt_r 0.65868099/0.43241432n 0.47370222/1.0502583n 0.81473466/0.23200043n
R_load = 50
[Rising Waveform]
R_fixture = 50
V_fixture = 1.8
V_fixture_min = 1.62
V_fixture_max = 1.98
0s        710.5mV    852.8mV    640.5mV
228.5ps   710.5mV    852.8mV    729.4mV
279ps     716.3mV    852.8mV    899.8mV
463.3ps   770.6mV    853.1mV    1.785V
615.2ps   1.065V     864.8mV    1.938V
839.3ps   1.625V     922.4mV    1.966V
1.066ns   1.763V     1.137V     1.974V
1.387ns   1.787V     1.472V     1.978V
1.76ns    1.794V     1.574V     1.979V
4.974ns   1.8V       1.618V     1.98V
[Rising Waveform]
R_fixture = 50
V_fixture = 0
V_fixture_min = 0
V_fixture_max = 0
0s        0V         0V         2.094mV
279.1ps   -2.515mV   0V         58.4mV
573.7ps   12.82mV    0V         1.07V
671.4ps   117.4mV    0V         1.206V
830.2ps   368.9mV    0V         1.282V
1.156ns   859.5mV    0V         1.326V
1.545ns   1.016V     77.11mV    1.344V
2.456ns   1.074V     517.8mV    1.35V
2.875ns   1.082V     641.9mV    1.35V
5.077ns   1.088V     756mV      1.35V
[Falling Waveform]
R_fixture = 50
V_fixture = 1.8
V_fixture_min = 1.62
V_fixture_max = 1.98
0s        1.801V     1.62V      1.98V
369.4ps   1.801V     1.62V      1.862V
442.6ps   1.801V     1.62V      1.671V
619.8ps   1.798V     1.62V      837.9mV
786.4ps   1.667V     1.62V      692.8mV
1.132ns   940.9mV    1.62V      653.8mV
1.38ns    776.4mV    1.62V      647.1mV
1.681ns   737.8mV    1.572V     643.2mV
2.85ns    713.9mV    952.9mV    639.9mV
4.974ns   710.2mV    860.2mV    639.7mV
[Falling Waveform]
R_fixture = 50
V_fixture = 0
V_fixture_min = 0
V_fixture_max = 0
0s        1.087V     769.3mV    1.349V
330.5ps   1.087V     769.3mV    1.237V
405.9ps   1.087V     769.3mV    1.014V
559.3ps   1.051V     769.3mV    204.2mV
687.6ps   924.3mV    769.3mV    48.72mV
961.4ps   173.8mV    763.3mV    18.47mV
1.114ns   46.42mV    739.6mV    13.65mV
1.361ns   22.55mV    645.9mV    7.306mV
2.114ns   7.538mV    42.08mV    3.028mV
5.077ns   2.086mV    3.288mV    2.564mV
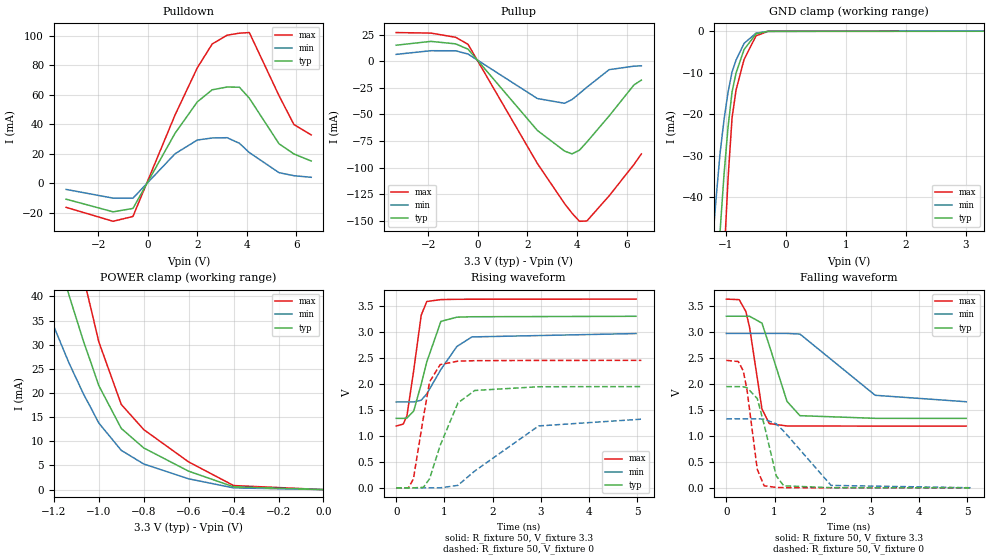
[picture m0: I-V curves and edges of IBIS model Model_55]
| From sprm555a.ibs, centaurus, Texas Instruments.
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| Model based on original model for BC1833DV40DCMLBPBFBP18LL_SSDHH
|   Sub model BC40DCM_H_PUPDOFF_10P_SC1_3P3
[model]   Model_55
|[Description]  [3.3V-I/O-PI-SLOW, IND, 10%]
|   Slow slew rate (SC1 = 1),Weak pull up/down disabled,Industrial
|   temperature range (-40C to 125C, 25C nominal),10% power supply
|   tolerance
|[Input Load]   PI
|[Output Drive] SLOW
|Voltage   3.3V
|Mode   I/O
Model_type   I/O
Polarity   Non-Inverting
Enable   Active-Low
Vinl =  0.8V
Vinh =  2V
Cref =  15pF
Rref =  100.0000M
Vref =  0V
Vmeas =  1.65
C_comp   2.113067p   1.963632p   2.200199p
[Model Spec]
Vinl   0.8V   0.8V   0.8V
Vinh   2V   2V   2V
[Temperature Range]   25   125   -40
[Voltage Range]   3.3   2.97   3.63
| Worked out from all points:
|   slope of the pulldown table from 0 to 0.495 V, typ, clamps not added: 31.8 ohm
|   slope of the pullup table from 0 to 0.495 V, typ, clamps not added: 33.8 ohm
|   GND clamp passes 1 mA (typ) near -0.53 V on its own axis
|   POWER clamp passes 1 mA (typ) near -0.43 V on its own axis
|   rising waveform, R_fixture 50, V_fixture 3.3: 20-80 % time 338ps typ, 538ps min, 211ps max; typ from 1.34 V to 3.3 V
|   rising waveform, R_fixture 50, V_fixture 0: 20-80 % time 469ps typ, 1.07ns min, 245ps max; typ from 0 V to 1.95 V
|   falling waveform, R_fixture 50, V_fixture 3.3: 20-80 % time 389ps typ, 938ps min, 235ps max; typ from 3.3 V to 1.34 V
|   falling waveform, R_fixture 50, V_fixture 0: 20-80 % time 295ps typ, 648ps min, 202ps max; typ from 1.95 V to 0 V
[POWER_clamp]
-3.3V     446.9mA    419.5mA    603.9mA
-1.267V   62.17mA    41.5mA     88.03mA
-1.233V   56.52mA    37.5mA     80.22mA
-1.133V   40.34mA    26.27mA    57.61mA
-1.067V   30.56mA    19.7mA     43.68mA
-1.033V   26.05mA    16.75mA    37.15mA
-1V       21.55mA    13.8mA     30.62mA
-900mV    12.68mA    8.135mA    17.65mA
-800mV    8.63mA     5.309mA    12.43mA
-600mV    3.813mA    2.231mA    5.733mA
-400mV    580.7uA    357.1uA    842.6uA
0V        4.589uA    2.01uA     9.301uA
[Pulldown]
-3.3V     -10.93mA   -4.311mA   -16.48mA
-1.4V     -19.53mA   -10.23mA   -25.96mA
-600mV    -17.23mA   -10.26mA   -22.66mA
1.1V      33.82mA    19.89mA    46.25mA
2V        55.14mA    29.24mA    78.29mA
2.6V      63.35mA    30.61mA    94.45mA
3.2V      65.21mA    30.81mA    100.4mA
3.7V      65.09mA    27.02mA    101.8mA
4.1V      57.63mA    20.71mA    102.2mA
5.3V      26.68mA    7.058mA    59.31mA
5.9V      19.77mA    5.007mA    39.76mA
6.6V      14.97mA    3.923mA    32.7mA
[Pullup]
-3.3V     15.12mA    6.498mA    27.02mA
-1.9V     18.73mA    9.943mA    26.53mA
-900mV    16.4mA     9.888mA    22.58mA
-400mV    11.39mA    6.786mA    15.98mA
2.4V      -65.08mA   -35.06mA   -96.18mA
3.5V      -84.52mA   -39.53mA   -134mA
3.8V      -87.17mA   -36.01mA   -143mA
4.1V      -83.69mA   -30.35mA   -150.6mA
4.4V      -75.99mA   -24.42mA   -150.3mA
5.3V      -51.41mA   -7.872mA   -126.6mA
6.3V      -22.29mA   -4.606mA   -97.15mA
6.6V      -17.71mA   -4.277mA   -87.2mA
[GND_clamp]
-3.3V     -787.2mA   -607.8mA   -1.235A
-1.233V   -85.66mA   -52.14mA   -138.8mA
-1.167V   -66.47mA   -40.37mA   -107.7mA
-1.1V     -48.25mA   -29.37mA   -77.98mA
-1.033V   -34.27mA   -21.19mA   -54.56mA
-966.7mV  -23.06mA   -14.66mA   -35.51mA
-900mV    -14.61mA   -9.789mA   -20.83mA
-833.3mV  -10.05mA   -6.934mA   -14.15mA
-700mV    -4.416mA   -2.931mA   -6.811mA
-500mV    -621.6uA   -443.4uA   -1.094mA
-300mV    -17.13uA   -24.29uA   -23.57uA
3.3V      4.589uA    110.6uA    5.608uA
[Ramp]
dV/dt_f  1.1805286/0.38922465n 0.79479739/0.94637031n  1.4675322/0.23563742n
dV/dt_r  1.1741804/0.47064594n 0.80302841/1.0833446n   1.476879/0.24629464n
R_load = 50
[Rising Waveform]
R_fixture = 50
V_fixture = 3.3
V_fixture_min = 2.97
V_fixture_max = 3.63
0s        1.337V     1.652V     1.189V
145.8ps   1.337V     1.652V     1.227V
222.2ps   1.343V     1.652V     1.385V
363.2ps   1.478V     1.652V     2.26V
518.4ps   1.994V     1.686V     3.321V
633.4ps   2.42V      1.807V     3.584V
926.6ps   3.202V     2.277V     3.621V
1.259ns   3.283V     2.72V      3.627V
1.569ns   3.291V     2.903V     3.628V
4.974ns   3.3V       2.968V     3.63V
[Rising Waveform]
R_fixture = 50
V_fixture = 0
V_fixture_min = 0
V_fixture_max = 0
0s        0V         0V         0V
251.7ps   0V         0V         0V
356ps     0V         0V         168.4mV
565.6ps   11.05mV    0V         1.363V
691.9ps   174.5mV    0V         2.039V
912.8ps   819.3mV    0V         2.372V
1.28ns    1.633V     48.22mV    2.437V
1.628ns   1.873V     323.8mV    2.446V
2.953ns   1.945V     1.191V     2.451V
5.084ns   1.948V     1.321V     2.452V
[Falling Waveform]
R_fixture = 50
V_fixture = 3.3
V_fixture_min = 2.97
V_fixture_max = 3.63
0s        3.3V       2.969V     3.629V
266.3ps   3.3V       2.969V     3.619V
404.6ps   3.3V       2.969V     3.392V
481.8ps   3.3V       2.969V     3.088V
738.8ps   3.167V     2.969V     1.517V
889.9ps   2.74V      2.969V     1.236V
1.258ns   1.663V     2.969V     1.19V
1.527ns   1.388V     2.957V     1.189V
3.087ns   1.337V     1.78V      1.188V
4.974ns   1.336V     1.656V     1.188V
[Falling Waveform]
R_fixture = 50
V_fixture = 0
V_fixture_min = 0
V_fixture_max = 0
0s        1.947V     1.328V     2.451V
249.3ps   1.947V     1.328V     2.429V
350.8ps   1.943V     1.328V     2.25V
430.2ps   1.925V     1.328V     1.875V
641.7ps   1.717V     1.328V     354mV
784.5ps   1.215V     1.32V      39.9mV
1.034ns   233.1mV    1.232V     8.205mV
1.19ns    39.02mV    1.09V      4.373mV
2.172ns   3.797mV    47.17mV    0V
5.084ns   0V         2.119mV    0V
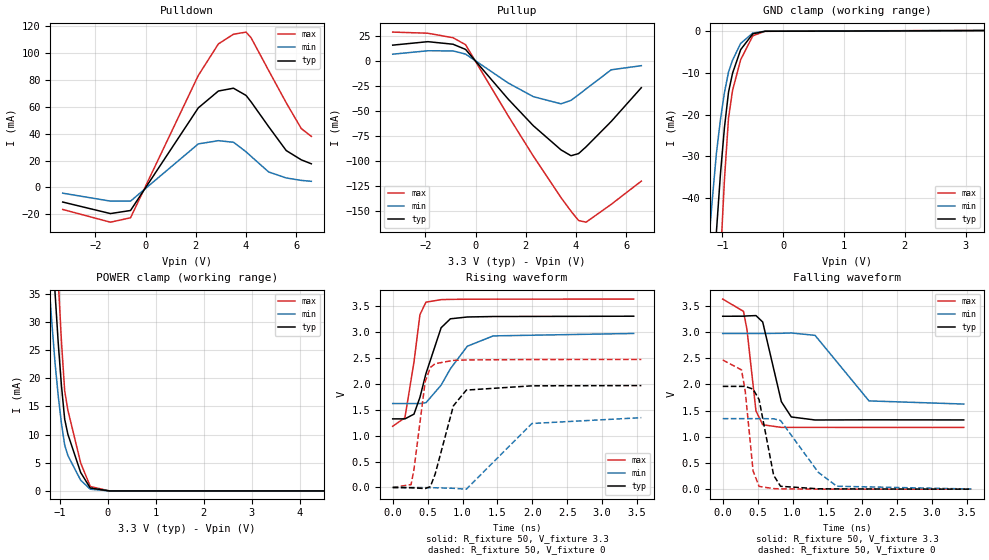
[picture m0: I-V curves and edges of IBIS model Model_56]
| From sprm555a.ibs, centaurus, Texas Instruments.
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| Model based on original model for BC1833DV40DCMLBPBFBP18LL_SSDHH
|   Sub model BC40DCM_H_PD_ON_10P_!SC1_3P3
[model]   Model_56
|[Description]  [3.3V-I/O-PD-FAST, IND, 10%]
|   Fast slew rate (SC1 = 0),Weak internal pull-down,Industrial
|   temperature range (-40C to 125C, 25C nominal),10% power supply
|   tolerance
|[Input Load]   PD
|[Output Drive] FAST
|Voltage   3.3V
|Mode   I/O
Model_type   I/O
Polarity   Non-Inverting
Enable   Active-Low
Vinl =  0.8V
Vinh =  2V
Cref =  15pF
Rref =  100.0000M
Vref =  0V
Vmeas =  1.65
C_comp   2.113067p   1.963632p   2.200199p
[Model Spec]
Vinl   0.8V   0.8V   0.8V
Vinh   2V   2V   2V
[Temperature Range]   25   125   -40
[Voltage Range]   3.3   2.97   3.63
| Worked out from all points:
|   slope of the pulldown table from 0 to 0.495 V, typ, clamps not added: 31.8 ohm
|   slope of the pullup table from 0 to 0.495 V, typ, clamps not added: 33.3 ohm
|   GND clamp passes 1 mA (typ) near -0.52 V on its own axis
|   POWER clamp passes 1 mA (typ) near -0.42 V on its own axis
|   rising waveform, R_fixture 50, V_fixture 3.3: 20-80 % time 258ps typ, 391ps min, 146ps max; typ from 1.32 V to 3.3 V
|   rising waveform, R_fixture 50, V_fixture 0: 20-80 % time 233ps typ, 479ps min, 138ps max; typ from 0 V to 1.96 V
|   falling waveform, R_fixture 50, V_fixture 3.3: 20-80 % time 199ps typ, 427ps min, 119ps max; typ from 3.3 V to 1.32 V
|   falling waveform, R_fixture 50, V_fixture 0: 20-80 % time 162ps typ, 386ps min, 107ps max; typ from 1.96 V to 0 V
[POWER_clamp]
-3.3V     446.9mA    419.5mA    603.9mA
-1.233V   56.59mA    37.53mA    80.37mA
-1.167V   45.68mA    29.91mA    65.17mA
-1.1V     35.14mA    22.67mA    50.36mA
-1.033V   26.13mA    16.78mA    37.31mA
-966.7mV  18.67mA    11.95mA    26.46mA
-900mV    12.76mA    8.172mA    17.82mA
-833.3mV  10.07mA    6.29mA     14.35mA
-566.7mV  3.276mA    1.904mA    4.983mA
-366.7mV  519.9uA    307.2uA    792.3uA
33.33mV   0A         0A         0A
6.6V      0A         0A         0A
[Pulldown]
-3.3V     -10.92mA   -4.307mA   -16.45mA
-1.4V     -19.52mA   -10.22mA   -25.94mA
-600mV    -17.22mA   -10.25mA   -22.66mA
2.1V      59.3mA     32.44mA    83.48mA
2.9V      71.86mA    34.84mA    107mA
3.5V      73.95mA    33.66mA    114.2mA
4V        68.6mA     26.56mA    115.8mA
4.2V      63.8mA     23.19mA    111.6mA
4.9V      45.33mA    11.53mA    87.2mA
5.6V      27.47mA    7.046mA    63.1mA
6.2V      20.56mA    5.221mA    43.87mA
6.6V      17.6mA     4.555mA    38.05mA
[Pullup]
-3.3V     15.77mA    6.741mA    28.8mA
-1.9V     19.23mA    10.15mA    27.67mA
-900mV    16.69mA    10.02mA    23.17mA
-400mV    11.53mA    6.853mA    16.25mA
1.3V      -38.16mA   -22.04mA   -54.89mA
2.3V      -64.7mA    -35.66mA   -95.04mA
3.4V      -88.76mA   -42.82mA   -136.4mA
3.8V      -94.64mA   -39.36mA   -150mA
4.1V      -92.53mA   -33.79mA   -159.3mA
4.4V      -85.77mA   -27.94mA   -161mA
5.4V      -60.46mA   -8.849mA   -143.2mA
6.6V      -26.71mA   -4.741mA   -120mA
[GND_clamp]
-3.3V     -787.2mA   -607.8mA   -1.235A
-1.233V   -85.66mA   -52.14mA   -138.8mA
-1.167V   -66.47mA   -40.37mA   -107.7mA
-1.1V     -48.25mA   -29.37mA   -77.99mA
-1.033V   -34.28mA   -21.19mA   -54.56mA
-966.7mV  -23.07mA   -14.67mA   -35.51mA
-900mV    -14.62mA   -9.792mA   -20.84mA
-833.3mV  -10.07mA   -6.938mA   -14.17mA
-700mV    -4.435mA   -2.939mA   -6.836mA
-500mV    -641.2uA   -454.5uA   -1.12mA
-300mV    -31.62uA   -32.73uA   -44.27uA
3.3V      108.6uA    159.4uA    198.5uA
[Ramp]
dV/dt_f  1.1954671/0.20067558n 0.83578416/0.44375385n  1.4750939/0.1196438n
dV/dt_r   1.191634/0.23557539n 0.82814083/0.49046564n  1.4892899/0.13871809n
R_load = 50
[Rising Waveform]
R_fixture = 50
V_fixture = 3.3
V_fixture_min = 2.97
V_fixture_max = 3.63
0s        1.321V     1.616V     1.179V
174.9ps   1.321V     1.616V     1.343V
304.7ps   1.412V     1.616V     2.414V
390.3ps   1.736V     1.616V     3.328V
476.4ps   2.193V     1.632V     3.567V
693.7ps   3.075V     1.97V      3.616V
826.4ps   3.247V     2.285V     3.621V
1.069ns   3.282V     2.719V     3.624V
1.44ns    3.291V     2.918V     3.625V
3.453ns   3.297V     2.965V     3.627V
[Rising Waveform]
R_fixture = 50
V_fixture = 0
V_fixture_min = 0
V_fixture_max = 0
0s        0V         0V         0V
263.3ps   -5.429mV   0V         55.99mV
302.8ps   -7.294mV   0V         330.8mV
464.7ps   -20.45mV   -2.386mV   2.033V
539.4ps   17.49mV    -3.793mV   2.311V
608.1ps   257.7mV    -5.574mV   2.384V
869.8ps   1.573V     -15.1mV    2.447V
1.055ns   1.875V     -32.12mV   2.455V
1.995ns   1.957V     1.232V     2.463V
3.562ns   1.962V     1.344V     2.465V
[Falling Waveform]
R_fixture = 50
V_fixture = 3.3
V_fixture_min = 2.97
V_fixture_max = 3.63
0s        3.299V     2.97V      3.627V
297.6ps   3.3V       2.97V      3.393V
347.2ps   3.305V     2.97V      3.049V
476.6ps   3.312V     2.97V      1.493V
573.1ps   3.189V     2.97V      1.229V
840.4ps   1.669V     2.974V     1.179V
982.6ps   1.378V     2.98V      1.179V
1.323ns   1.32V      2.935V     1.179V
2.096ns   1.323V     1.684V     1.178V
3.453ns   1.321V     1.624V     1.178V
[Falling Waveform]
R_fixture = 50
V_fixture = 0
V_fixture_min = 0
V_fixture_max = 0
0s        1.961V     1.346V     2.465V
269.5ps   1.961V     1.346V     2.276V
323.1ps   1.96V      1.346V     1.867V
434.8ps   1.909V     1.346V     349.3mV
521.3ps   1.709V     1.346V     52.18mV
729.7ps   264.8mV    1.343V     10.77mV
829ps     54.5mV     1.31V      5.963mV
1.369ns   7.062mV    322.7mV    0V
1.636ns   4.788mV    55.5mV     0V
3.562ns   0V         2.905mV    0V
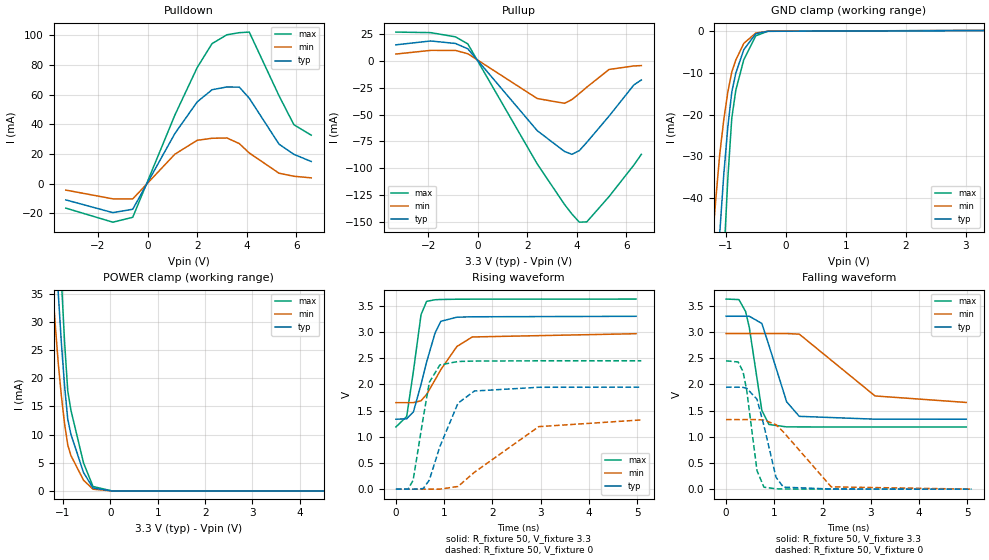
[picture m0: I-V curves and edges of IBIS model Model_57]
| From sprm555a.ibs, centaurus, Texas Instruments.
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| Model based on original model for BC1833DV40DCMLBPBFBP18LL_SSDHH
|   Sub model BC40DCM_H_PD_ON_10P_SC1_3P3
[model]   Model_57
|[Description]  [3.3V-I/O-PD-SLOW, IND, 10%]
|   Slow slew rate (SC1 = 1),Weak internal pull-down,Industrial
|   temperature range (-40C to 125C, 25C nominal),10% power supply
|   tolerance
|[Input Load]   PD
|[Output Drive] SLOW
|Voltage   3.3V
|Mode   I/O
Model_type   I/O
Polarity   Non-Inverting
Enable   Active-Low
Vinl =  0.8V
Vinh =  2V
Cref =  15pF
Rref =  100.0000M
Vref =  0V
Vmeas =  1.65
C_comp   2.113067p   1.963632p   2.200199p
[Model Spec]
Vinl   0.8V   0.8V   0.8V
Vinh   2V   2V   2V
[Temperature Range]   25   125   -40
[Voltage Range]   3.3   2.97   3.63
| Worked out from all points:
|   slope of the pulldown table from 0 to 0.495 V, typ, clamps not added: 31.8 ohm
|   slope of the pullup table from 0 to 0.495 V, typ, clamps not added: 33.8 ohm
|   GND clamp passes 1 mA (typ) near -0.52 V on its own axis
|   POWER clamp passes 1 mA (typ) near -0.42 V on its own axis
|   rising waveform, R_fixture 50, V_fixture 3.3: 20-80 % time 338ps typ, 538ps min, 211ps max; typ from 1.33 V to 3.3 V
|   rising waveform, R_fixture 50, V_fixture 0: 20-80 % time 469ps typ, 1.07ns min, 245ps max; typ from 0 V to 1.95 V
|   falling waveform, R_fixture 50, V_fixture 3.3: 20-80 % time 388ps typ, 938ps min, 235ps max; typ from 3.3 V to 1.33 V
|   falling waveform, R_fixture 50, V_fixture 0: 20-80 % time 295ps typ, 648ps min, 202ps max; typ from 1.95 V to 0 V
[POWER_clamp]
-3.3V     446.9mA    419.5mA    603.9mA
-1.233V   56.59mA    37.53mA    80.37mA
-1.167V   45.68mA    29.91mA    65.17mA
-1.1V     35.14mA    22.67mA    50.36mA
-1.033V   26.13mA    16.78mA    37.31mA
-966.7mV  18.67mA    11.95mA    26.46mA
-900mV    12.76mA    8.172mA    17.82mA
-833.3mV  10.07mA    6.29mA     14.35mA
-566.7mV  3.276mA    1.904mA    4.983mA
-366.7mV  519.9uA    307.2uA    792.3uA
33.33mV   0A         0A         0A
6.6V      0A         0A         0A
[Pulldown]
-3.3V     -10.93mA   -4.311mA   -16.48mA
-1.4V     -19.53mA   -10.23mA   -25.96mA
-600mV    -17.23mA   -10.26mA   -22.66mA
1.1V      33.82mA    19.89mA    46.25mA
2V        55.14mA    29.24mA    78.29mA
2.6V      63.35mA    30.61mA    94.44mA
3.2V      65.21mA    30.81mA    100.4mA
3.7V      65.09mA    27.02mA    101.8mA
4.1V      57.64mA    20.71mA    102.2mA
5.3V      26.68mA    7.058mA    59.31mA
5.9V      19.77mA    5.007mA    39.76mA
6.6V      14.97mA    3.923mA    32.7mA
[Pullup]
-3.3V     15.12mA    6.498mA    27.02mA
-1.9V     18.73mA    9.943mA    26.53mA
-900mV    16.4mA     9.888mA    22.58mA
-400mV    11.39mA    6.786mA    15.98mA
2.4V      -65.08mA   -35.06mA   -96.18mA
3.5V      -84.52mA   -39.53mA   -134mA
3.8V      -87.17mA   -36.01mA   -143mA
4.1V      -83.69mA   -30.35mA   -150.6mA
4.4V      -75.99mA   -24.42mA   -150.3mA
5.3V      -51.41mA   -7.872mA   -126.6mA
6.3V      -22.29mA   -4.606mA   -97.15mA
6.6V      -17.71mA   -4.277mA   -87.2mA
[GND_clamp]
-3.3V     -787.2mA   -607.8mA   -1.235A
-1.233V   -85.66mA   -52.14mA   -138.8mA
-1.167V   -66.47mA   -40.37mA   -107.7mA
-1.1V     -48.25mA   -29.37mA   -77.99mA
-1.033V   -34.28mA   -21.19mA   -54.56mA
-966.7mV  -23.07mA   -14.67mA   -35.51mA
-900mV    -14.62mA   -9.792mA   -20.84mA
-833.3mV  -10.07mA   -6.938mA   -14.17mA
-700mV    -4.435mA   -2.939mA   -6.836mA
-500mV    -641.2uA   -454.5uA   -1.12mA
-300mV    -31.62uA   -32.73uA   -44.27uA
3.3V      108.6uA    159.4uA    198.5uA
[Ramp]
dV/dt_f  1.1800079/0.3886504n 0.79472193/0.94572277n  1.4664239/0.23531379n
dV/dt_r  1.1731171/0.47012806n 0.80241594/1.0823663n  1.4753439/0.24599817n
R_load = 50
[Rising Waveform]
R_fixture = 50
V_fixture = 3.3
V_fixture_min = 2.97
V_fixture_max = 3.63
0s        1.335V     1.651V     1.187V
222.7ps   1.342V     1.651V     1.385V
362.9ps   1.476V     1.651V     2.255V
520.9ps   2.002V     1.687V     3.332V
635.3ps   2.425V     1.808V     3.583V
810.9ps   2.979V     2.086V     3.614V
930.2ps   3.203V     2.281V     3.619V
1.263ns   3.281V     2.722V     3.624V
1.581ns   3.289V     2.904V     3.625V
4.974ns   3.298V     2.966V     3.627V
[Rising Waveform]
R_fixture = 50
V_fixture = 0
V_fixture_min = 0
V_fixture_max = 0
0s        0V         0V         0V
251.7ps   0V         0V         0V
356ps     0V         0V         168.4mV
565.6ps   11.05mV    0V         1.363V
691.9ps   174.5mV    0V         2.039V
910.3ps   812.5mV    0V         2.37V
1.286ns   1.641V     51.5mV     2.436V
1.628ns   1.873V     323.9mV    2.444V
2.959ns   1.944V     1.193V     2.449V
5.084ns   1.946V     1.321V     2.449V
[Falling Waveform]
R_fixture = 50
V_fixture = 3.3
V_fixture_min = 2.97
V_fixture_max = 3.63
0s        3.298V     2.968V     3.626V
266.3ps   3.298V     2.968V     3.616V
404.6ps   3.298V     2.968V     3.389V
481.9ps   3.298V     2.968V     3.083V
741.1ps   3.161V     2.968V     1.502V
888.5ps   2.742V     2.968V     1.234V
1.255ns   1.667V     2.968V     1.188V
1.517ns   1.389V     2.957V     1.187V
3.086ns   1.335V     1.778V     1.186V
4.974ns   1.334V     1.654V     1.186V
[Falling Waveform]
R_fixture = 50
V_fixture = 0
V_fixture_min = 0
V_fixture_max = 0
0s        1.945V     1.327V     2.448V
249.3ps   1.945V     1.327V     2.426V
350.8ps   1.941V     1.327V     2.247V
427ps     1.925V     1.327V     1.892V
641.4ps   1.715V     1.327V     352.6mV
785.2ps   1.21V      1.319V     37.65mV
1.035ns   226.7mV    1.23V      6.869mV
1.188ns   38.25mV    1.091V     3.372mV
2.179ns   3.051mV    44.29mV    0V
5.084ns   0V         0V         0V
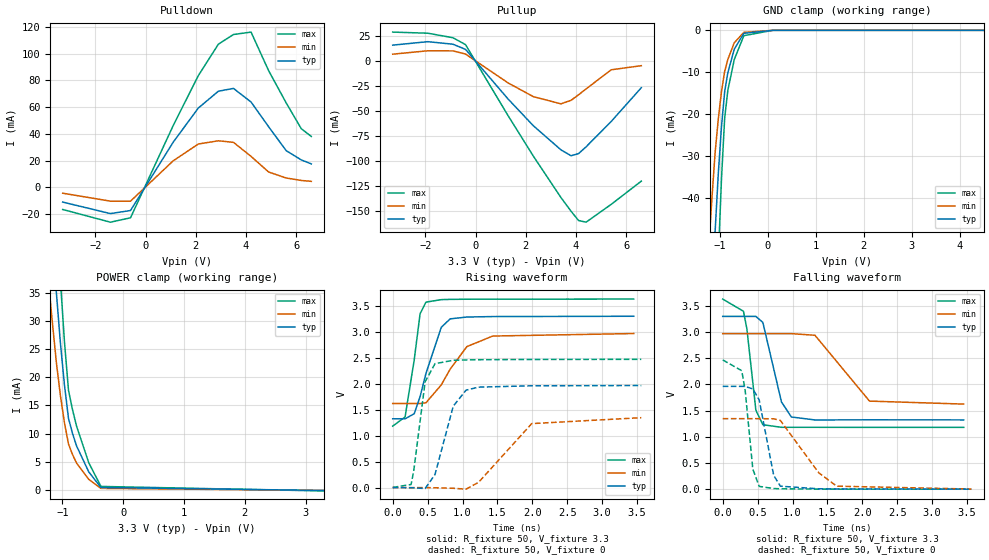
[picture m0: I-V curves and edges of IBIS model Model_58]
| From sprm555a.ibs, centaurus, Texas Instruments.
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| Model based on original model for BC1833DV40DCMLBPBFBP18LL_SSDHH
|   Sub model BC40DCM_H_PU_ON_10P_!SC1_3P3
[model]   Model_58
|[Description]  [3.3V-I/O-PU-FAST, IND, 10%]
|   Fast slew rate (SC1 = 0),Weak internal pull-up,Industrial
|   temperature range (-40C to 125C, 25C nominal),10% power supply
|   tolerance
|[Input Load]   PU
|[Output Drive] FAST
|Voltage   3.3V
|Mode   I/O
Model_type   I/O
Polarity   Non-Inverting
Enable   Active-Low
Vinl =  0.8V
Vinh =  2V
Cref =  15pF
Rref =  100.0000M
Vref =  0V
Vmeas =  1.65
C_comp   2.113067p   1.963632p   2.200199p
[Model Spec]
Vinl   0.8V   0.8V   0.8V
Vinh   2V   2V   2V
[Temperature Range]   25   125   -40
[Voltage Range]   3.3   2.97   3.63
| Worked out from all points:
|   slope of the pulldown table from 0 to 0.495 V, typ, clamps not added: 31.8 ohm
|   slope of the pullup table from 0 to 0.495 V, typ, clamps not added: 33.3 ohm
|   GND clamp passes 1 mA (typ) near -0.52 V on its own axis
|   POWER clamp passes 1 mA (typ) near -0.43 V on its own axis
|   rising waveform, R_fixture 50, V_fixture 3.3: 20-80 % time 258ps typ, 390ps min, 146ps max; typ from 1.32 V to 3.3 V
|   rising waveform, R_fixture 50, V_fixture 0: 20-80 % time 233ps typ, 479ps min, 138ps max; typ from 0 V to 1.97 V
|   falling waveform, R_fixture 50, V_fixture 3.3: 20-80 % time 199ps typ, 427ps min, 119ps max; typ from 3.3 V to 1.32 V
|   falling waveform, R_fixture 50, V_fixture 0: 20-80 % time 162ps typ, 386ps min, 107ps max; typ from 1.96 V to 0.003 V
[POWER_clamp]
-3.3V     446.9mA    419.5mA    603.9mA
-1.233V   56.55mA    37.52mA    80.26mA
-1.167V   45.63mA    29.9mA     65.05mA
-1.1V     35.1mA     22.66mA    50.24mA
-1.033V   26.08mA    16.76mA    37.18mA
-966.7mV  18.62mA    11.92mA    26.33mA
-900mV    12.7mA     8.149mA    17.69mA
-833.3mV  10mA       6.265mA    14.21mA
-766.7mV  7.795mA    4.753mA    11.3mA
-566.7mV  3.199mA    1.871mA    4.823mA
-366.7mV  433.5uA    268.4uA    618.3uA
3.3V      -100.3uA   -83.23uA   -188.3uA
[Pulldown]
-3.3V     -10.92mA   -4.307mA   -16.45mA
-1.4V     -19.52mA   -10.22mA   -25.94mA
-600mV    -17.22mA   -10.25mA   -22.66mA
1.1V      33.8mA     19.88mA    46.22mA
2.1V      59.3mA     32.44mA    83.48mA
2.9V      71.86mA    34.84mA    107mA
3.5V      73.95mA    33.66mA    114.2mA
4.2V      63.8mA     23.19mA    116mA
4.9V      45.33mA    11.53mA    87.2mA
5.6V      27.47mA    7.046mA    63.1mA
6.2V      20.56mA    5.221mA    43.87mA
6.6V      17.6mA     4.555mA    38.05mA
[Pullup]
-3.3V     15.77mA    6.741mA    28.8mA
-1.9V     19.23mA    10.15mA    27.67mA
-900mV    16.69mA    10.02mA    23.17mA
-400mV    11.53mA    6.853mA    16.25mA
1.3V      -38.16mA   -22.04mA   -54.88mA
2.3V      -64.7mA    -35.66mA   -95.04mA
3.4V      -88.76mA   -42.82mA   -136.4mA
3.8V      -94.64mA   -39.36mA   -150mA
4.1V      -92.53mA   -33.79mA   -159.3mA
4.4V      -85.77mA   -27.94mA   -161mA
5.4V      -60.46mA   -8.849mA   -143.2mA
6.6V      -26.71mA   -4.741mA   -120mA
[GND_clamp]
-3.3V     -787.2mA   -607.8mA   -1.235A
-1.233V   -85.67mA   -52.14mA   -138.8mA
-1.167V   -66.48mA   -40.37mA   -107.8mA
-1.1V     -48.26mA   -29.37mA   -78.02mA
-1.033V   -34.3mA    -21.2mA    -54.63mA
-966.7mV  -23.1mA    -14.67mA   -35.61mA
-900mV    -14.66mA   -9.802mA   -20.96mA
-833.3mV  -10.12mA   -6.954mA   -14.3mA
-700mV    -4.501mA   -2.964mA   -6.982mA
-500mV    -717.7uA   -486.4uA   -1.28mA
100mV     0A         0A         0A
6.6V      0A         0A         0A
[Ramp]
dV/dt_f  1.1949878/0.20073041n 0.83561812/0.44379117n  1.4746319/0.11970062n
dV/dt_r  1.1920116/0.23559687n 0.82831344/0.49060999n  1.4896482/0.13867294n
R_load = 50
[Rising Waveform]
R_fixture = 50
V_fixture = 3.3
V_fixture_min = 2.97
V_fixture_max = 3.63
0s        1.324V     1.618V     1.183V
177.2ps   1.324V     1.618V     1.36V
308ps     1.422V     1.618V     2.456V
392.2ps   1.751V     1.618V     3.348V
476.8ps   2.2V       1.634V     3.571V
695.7ps   3.086V     1.977V     3.619V
823.7ps   3.249V     2.282V     3.624V
1.063ns   3.284V     2.715V     3.627V
1.433ns   3.293V     2.918V     3.628V
3.453ns   3.299V     2.966V     3.63V
[Rising Waveform]
R_fixture = 50
V_fixture = 0
V_fixture_min = 0
V_fixture_max = 0
0s        0V         0V         2.549mV
263.3ps   -3.484mV   0V         59.49mV
300.8ps   -5.235mV   0V         315.8mV
464.7ps   -18.21mV   0V         2.038V
606.2ps   252.2mV    -4.324mV   2.386V
867.5ps   1.568V     -13.57mV   2.451V
1.051ns   1.876V     -30.66mV   2.458V
1.23ns    1.934V     101.2mV    2.462V
1.992ns   1.96V      1.232V     2.467V
3.562ns   1.965V     1.346V     2.469V
[Falling Waveform]
R_fixture = 50
V_fixture = 3.3
V_fixture_min = 2.97
V_fixture_max = 3.63
0s        3.299V     2.97V      3.63V
297.6ps   3.299V     2.97V      3.397V
346.4ps   3.299V     2.97V      3.062V
475ps     3.299V     2.97V      1.51V
575.3ps   3.184V     2.97V      1.232V
842ps     1.666V     2.97V      1.183V
983.8ps   1.38V      2.97V      1.183V
1.322ns   1.323V     2.939V     1.183V
2.103ns   1.326V     1.683V     1.182V
3.453ns   1.324V     1.626V     1.182V
[Falling Waveform]
R_fixture = 50
V_fixture = 0
V_fixture_min = 0
V_fixture_max = 0
0s        1.964V     1.348V     2.469V
273.1ps   1.964V     1.348V     2.263V
322.1ps   1.963V     1.348V     1.883V
431ps     1.915V     1.348V     387.6mV
522.2ps   1.709V     1.348V     55.72mV
730.2ps   266.1mV    1.345V     14.58mV
826.7ps   58.95mV    1.313V     9.812mV
1.374ns   9.593mV    318.1mV    3.887mV
1.633ns   7.34mV     59.64mV    3.358mV
3.562ns   2.504mV    4.436mV    3.076mV
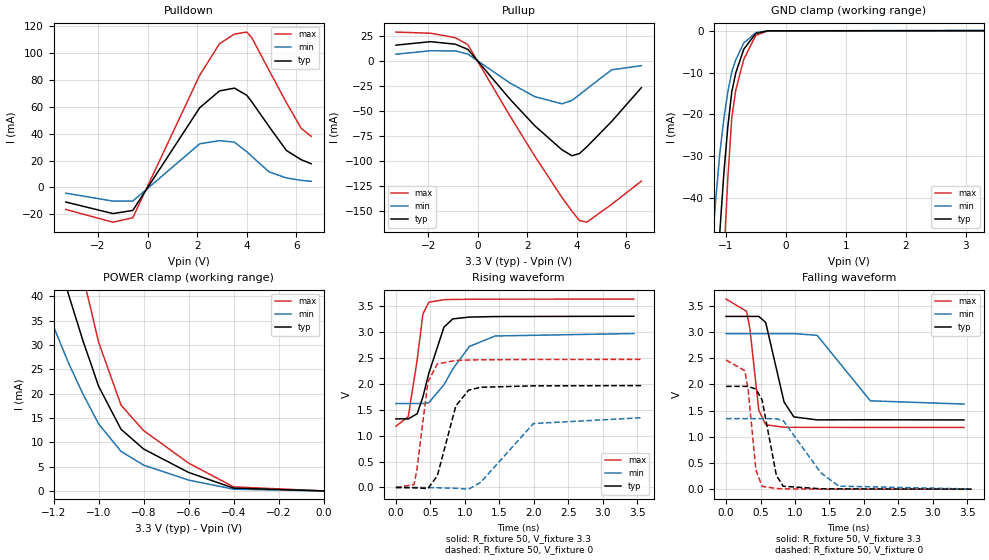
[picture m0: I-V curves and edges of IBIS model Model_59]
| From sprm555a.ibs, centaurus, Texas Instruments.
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| Model based on original model for BC1833DV40DCMLBPBFBP18LL_SSDHH
|   Sub model BC40DCM_H_PUPDOFF_10P_!SC1_3P3
[model]   Model_59
|[Description]  [3.3V-I/O-PI-FAST, IND, 10%]
|   Fast slew rate (SC1 = 0),Weak pull up/down disabled,Industrial
|   temperature range (-40C to 125C, 25C nominal),10% power supply
|   tolerance
|[Input Load]   PI
|[Output Drive] FAST
|Voltage   3.3V
|Mode   I/O
Model_type   I/O
Polarity   Non-Inverting
Enable   Active-Low
Vinl =  0.8V
Vinh =  2V
Cref =  15pF
Rref =  100.0000M
Vref =  0V
Vmeas =  1.65
C_comp   2.113067p   1.963632p   2.200199p
[Model Spec]
Vinl   0.8V   0.8V   0.8V
Vinh   2V   2V   2V
[Temperature Range]   25   125   -40
[Voltage Range]   3.3   2.97   3.63
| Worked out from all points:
|   slope of the pulldown table from 0 to 0.495 V, typ, clamps not added: 31.8 ohm
|   slope of the pullup table from 0 to 0.495 V, typ, clamps not added: 33.3 ohm
|   GND clamp passes 1 mA (typ) near -0.53 V on its own axis
|   POWER clamp passes 1 mA (typ) near -0.43 V on its own axis
|   rising waveform, R_fixture 50, V_fixture 3.3: 20-80 % time 258ps typ, 390ps min, 146ps max; typ from 1.32 V to 3.3 V
|   rising waveform, R_fixture 50, V_fixture 0: 20-80 % time 233ps typ, 479ps min, 138ps max; typ from 0 V to 1.96 V
|   falling waveform, R_fixture 50, V_fixture 3.3: 20-80 % time 199ps typ, 427ps min, 119ps max; typ from 3.3 V to 1.32 V
|   falling waveform, R_fixture 50, V_fixture 0: 20-80 % time 162ps typ, 386ps min, 107ps max; typ from 1.96 V to 0 V
[POWER_clamp]
-3.3V     446.9mA    419.5mA    603.9mA
-1.267V   62.17mA    41.5mA     88.03mA
-1.233V   56.52mA    37.5mA     80.22mA
-1.133V   40.34mA    26.27mA    57.61mA
-1.067V   30.56mA    19.7mA     43.68mA
-1.033V   26.05mA    16.75mA    37.15mA
-1V       21.55mA    13.8mA     30.62mA
-900mV    12.68mA    8.135mA    17.65mA
-800mV    8.63mA     5.309mA    12.43mA
-600mV    3.813mA    2.231mA    5.733mA
-400mV    580.7uA    357.1uA    842.6uA
0V        4.589uA    2.01uA     9.301uA
[Pulldown]
-3.3V     -10.92mA   -4.307mA   -16.45mA
-1.4V     -19.52mA   -10.22mA   -25.94mA
-600mV    -17.22mA   -10.25mA   -22.66mA
2.1V      59.3mA     32.44mA    83.48mA
2.9V      71.86mA    34.84mA    107mA
3.5V      73.95mA    33.66mA    114.2mA
4V        68.6mA     26.56mA    115.7mA
4.2V      63.8mA     23.19mA    111.6mA
4.9V      45.33mA    11.53mA    87.2mA
5.6V      27.47mA    7.046mA    63.1mA
6.2V      20.56mA    5.221mA    43.87mA
6.6V      17.6mA     4.555mA    38.05mA
[Pullup]
-3.3V     15.77mA    6.741mA    28.8mA
-1.9V     19.23mA    10.15mA    27.67mA
-900mV    16.69mA    10.02mA    23.17mA
-400mV    11.53mA    6.853mA    16.25mA
1.3V      -38.16mA   -22.04mA   -54.89mA
2.3V      -64.7mA    -35.66mA   -95.04mA
3.4V      -88.76mA   -42.82mA   -136.4mA
3.8V      -94.64mA   -39.36mA   -150mA
4.1V      -92.52mA   -33.79mA   -159.3mA
4.4V      -85.77mA   -27.94mA   -161mA
5.4V      -60.46mA   -8.849mA   -143.2mA
6.6V      -26.71mA   -4.741mA   -120mA
[GND_clamp]
-3.3V     -787.2mA   -607.8mA   -1.235A
-1.233V   -85.66mA   -52.14mA   -138.8mA
-1.167V   -66.47mA   -40.37mA   -107.7mA
-1.1V     -48.25mA   -29.37mA   -77.98mA
-1.033V   -34.27mA   -21.19mA   -54.56mA
-966.7mV  -23.06mA   -14.66mA   -35.51mA
-900mV    -14.61mA   -9.789mA   -20.83mA
-833.3mV  -10.05mA   -6.934mA   -14.15mA
-700mV    -4.416mA   -2.931mA   -6.81mA
-500mV    -621.6uA   -443.4uA   -1.094mA
-300mV    -17.13uA   -24.29uA   -23.57uA
3.3V      4.589uA    110.6uA    5.608uA
[Ramp]
dV/dt_f  1.1960233/0.20089183n 0.83592176/0.44389321n  1.4762062/0.11981459n
dV/dt_r  1.1926864/0.23585797n 0.82874501/0.49095814n   1.490806/0.13891221n
R_load = 50
[Rising Waveform]
R_fixture = 50
V_fixture = 3.3
V_fixture_min = 2.97
V_fixture_max = 3.63
0s        1.322V     1.617V     1.18V
178.7ps   1.322V     1.617V     1.364V
308ps     1.42V      1.617V     2.451V
391.5ps   1.745V     1.617V     3.339V
476.4ps   2.195V     1.633V     3.569V
697.5ps   3.089V     1.98V      3.618V
825ps     3.248V     2.283V     3.623V
1.066ns   3.283V     2.717V     3.626V
1.44ns    3.293V     2.919V     3.628V
3.453ns   3.299V     2.966V     3.63V
[Rising Waveform]
R_fixture = 50
V_fixture = 0
V_fixture_min = 0
V_fixture_max = 0
0s        0V         0V         0V
263.3ps   -5.429mV   0V         55.99mV
302.8ps   -7.295mV   0V         330.8mV
464.7ps   -20.45mV   -2.386mV   2.033V
601.3ps   227.1mV    -5.403mV   2.38V
869ps     1.57V      -15.05mV   2.448V
1.055ns   1.875V     -32.12mV   2.456V
1.23ns    1.931V     99.35mV    2.46V
1.995ns   1.958V     1.232V     2.466V
3.562ns   1.963V     1.344V     2.468V
[Falling Waveform]
R_fixture = 50
V_fixture = 3.3
V_fixture_min = 2.97
V_fixture_max = 3.63
0s        3.299V     2.97V      3.63V
297.6ps   3.299V     2.97V      3.397V
346.4ps   3.299V     2.97V      3.062V
475ps     3.299V     2.97V      1.509V
575.3ps   3.184V     2.97V      1.231V
842ps     1.665V     2.97V      1.181V
983.7ps   1.38V      2.97V      1.181V
1.322ns   1.323V     2.938V     1.181V
2.094ns   1.325V     1.687V     1.179V
3.453ns   1.322V     1.625V     1.179V
[Falling Waveform]
R_fixture = 50
V_fixture = 0
V_fixture_min = 0
V_fixture_max = 0
0s        1.963V     1.347V     2.467V
273.2ps   1.963V     1.347V     2.261V
322.1ps   1.962V     1.347V     1.882V
432.9ps   1.912V     1.347V     368.6mV
523ps     1.704V     1.347V     53.25mV
730.5ps   262.6mV    1.344V     12.33mV
829.6ps   55.76mV    1.31V      7.335mV
1.373ns   7.963mV    316.6mV    0V
1.634ns   5.657mV    57.58mV    0V
3.562ns   0V         3.208mV    0V
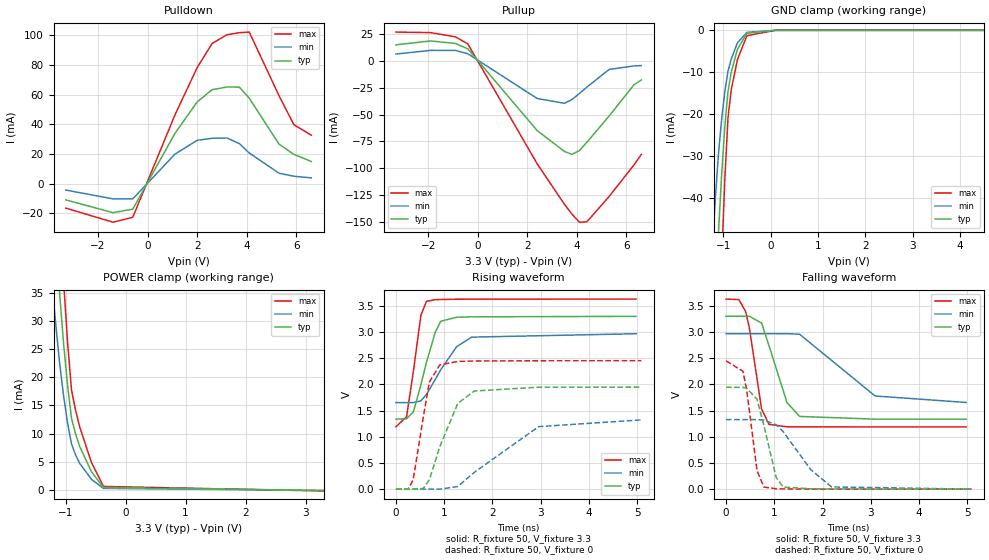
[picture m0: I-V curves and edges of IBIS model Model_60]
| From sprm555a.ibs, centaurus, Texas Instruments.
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| Model based on original model for BC1833DV40DCMLBPBFBP18LL_SSDHH
|   Sub model BC40DCM_H_PU_ON_10P_SC1_3P3
[model]   Model_60
|[Description]  [3.3V-I/O-PU-SLOW, IND, 10%]
|   Slow slew rate (SC1 = 1),Weak internal pull-up,Industrial
|   temperature range (-40C to 125C, 25C nominal),10% power supply
|   tolerance
|[Input Load]   PU
|[Output Drive] SLOW
|Voltage   3.3V
|Mode   I/O
Model_type   I/O
Polarity   Non-Inverting
Enable   Active-Low
Vinl =  0.8V
Vinh =  2V
Cref =  15pF
Rref =  100.0000M
Vref =  0V
Vmeas =  1.65
C_comp   2.113067p   1.963632p   2.200199p
[Model Spec]
Vinl   0.8V   0.8V   0.8V
Vinh   2V   2V   2V
[Temperature Range]   25   125   -40
[Voltage Range]   3.3   2.97   3.63
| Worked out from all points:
|   slope of the pulldown table from 0 to 0.495 V, typ, clamps not added: 31.8 ohm
|   slope of the pullup table from 0 to 0.495 V, typ, clamps not added: 33.8 ohm
|   GND clamp passes 1 mA (typ) near -0.52 V on its own axis
|   POWER clamp passes 1 mA (typ) near -0.43 V on its own axis
|   rising waveform, R_fixture 50, V_fixture 3.3: 20-80 % time 337ps typ, 537ps min, 211ps max; typ from 1.34 V to 3.3 V
|   rising waveform, R_fixture 50, V_fixture 0: 20-80 % time 469ps typ, 1.07ns min, 245ps max; typ from 0.003 V to 1.95 V
|   falling waveform, R_fixture 50, V_fixture 3.3: 20-80 % time 388ps typ, 938ps min, 235ps max; typ from 3.3 V to 1.34 V
|   falling waveform, R_fixture 50, V_fixture 0: 20-80 % time 295ps typ, 648ps min, 202ps max; typ from 1.95 V to 0.002 V
[POWER_clamp]
-3.3V     446.9mA    419.5mA    603.9mA
-1.233V   56.55mA    37.52mA    80.26mA
-1.167V   45.63mA    29.9mA     65.05mA
-1.1V     35.1mA     22.66mA    50.24mA
-1.033V   26.08mA    16.76mA    37.18mA
-966.7mV  18.62mA    11.92mA    26.33mA
-900mV    12.7mA     8.149mA    17.69mA
-833.3mV  10mA       6.265mA    14.21mA
-766.7mV  7.795mA    4.753mA    11.3mA
-566.7mV  3.199mA    1.871mA    4.823mA
-366.7mV  433.5uA    268.4uA    618.3uA
3.3V      -100.3uA   -83.23uA   -188.3uA
[Pulldown]
-3.3V     -10.93mA   -4.311mA   -16.48mA
-1.4V     -19.53mA   -10.23mA   -25.96mA
-600mV    -17.23mA   -10.26mA   -22.66mA
1.1V      33.82mA    19.89mA    46.25mA
2V        55.14mA    29.24mA    78.29mA
2.6V      63.35mA    30.61mA    94.45mA
3.2V      65.21mA    30.81mA    100.4mA
3.7V      65.09mA    27.02mA    101.8mA
4.1V      57.63mA    20.71mA    102.2mA
5.3V      26.68mA    7.058mA    59.31mA
5.9V      19.77mA    5.007mA    39.76mA
6.6V      14.97mA    3.923mA    32.7mA
[Pullup]
-3.3V     15.12mA    6.498mA    27.02mA
-1.9V     18.73mA    9.943mA    26.53mA
-900mV    16.4mA     9.888mA    22.58mA
-400mV    11.39mA    6.786mA    15.98mA
2.4V      -65.08mA   -35.06mA   -96.18mA
3.5V      -84.52mA   -39.53mA   -134mA
3.8V      -87.17mA   -36.01mA   -143mA
4.1V      -83.7mA    -30.35mA   -150.6mA
4.4V      -75.99mA   -24.42mA   -150.3mA
5.3V      -51.41mA   -7.872mA   -126.6mA
6.3V      -22.29mA   -4.606mA   -97.15mA
6.6V      -17.71mA   -4.277mA   -87.2mA
[GND_clamp]
-3.3V     -787.2mA   -607.8mA   -1.235A
-1.233V   -85.67mA   -52.14mA   -138.8mA
-1.167V   -66.48mA   -40.37mA   -107.8mA
-1.1V     -48.26mA   -29.37mA   -78.02mA
-1.033V   -34.3mA    -21.2mA    -54.63mA
-966.7mV  -23.1mA    -14.67mA   -35.61mA
-900mV    -14.66mA   -9.802mA   -20.96mA
-833.3mV  -10.12mA   -6.954mA   -14.3mA
-700mV    -4.501mA   -2.964mA   -6.982mA
-500mV    -717.7uA   -486.4uA   -1.28mA
100mV     0A         0A         0A
6.6V      0A         0A         0A
[Ramp]
dV/dt_f  1.1794553/0.38896266n   0.794154/0.94575733n  1.4659417/0.2354778n
dV/dt_r  1.1737439/0.4699587n 0.80293522/1.0826966n   1.475812/0.24584386n
R_load = 50
[Rising Waveform]
R_fixture = 50
V_fixture = 3.3
V_fixture_min = 2.97
V_fixture_max = 3.63
0s        1.338V     1.653V     1.191V
220.8ps   1.344V     1.653V     1.384V
362.4ps   1.479V     1.653V     2.258V
518ps     1.996V     1.687V     3.322V
633ps     2.422V     1.808V     3.586V
815.4ps   2.997V     2.096V     3.618V
930ps     3.207V     2.284V     3.622V
1.259ns   3.283V     2.721V     3.627V
1.568ns   3.291V     2.903V     3.628V
4.974ns   3.3V       2.968V     3.63V
[Rising Waveform]
R_fixture = 50
V_fixture = 0
V_fixture_min = 0
V_fixture_max = 0
0s        2.712mV    0V         3.379mV
251.7ps   2.712mV    0V         3.379mV
356ps     2.712mV    0V         171.8mV
566.1ps   13.38mV    0V         1.37V
692ps     177.3mV    0V         2.044V
908.8ps   811.8mV    0V         2.373V
1.281ns   1.637V     50.06mV    2.439V
1.626ns   1.875V     323.9mV    2.447V
2.957ns   1.947V     1.194V     2.452V
5.084ns   1.949V     1.323V     2.453V
[Falling Waveform]
R_fixture = 50
V_fixture = 3.3
V_fixture_min = 2.97
V_fixture_max = 3.63
0s        3.3V       2.969V     3.629V
266.3ps   3.3V       2.969V     3.619V
404.6ps   3.3V       2.969V     3.392V
481.8ps   3.3V       2.969V     3.088V
735.6ps   3.172V     2.969V     1.532V
889.9ps   2.74V      2.969V     1.238V
1.262ns   1.655V     2.969V     1.192V
1.523ns   1.39V      2.958V     1.191V
3.087ns   1.338V     1.78V      1.19V
4.974ns   1.338V     1.656V     1.19V
[Falling Waveform]
R_fixture = 50
V_fixture = 0
V_fixture_min = 0
V_fixture_max = 0
0s        1.948V     1.329V     2.452V
350.8ps   1.944V     1.329V     2.251V
427.6ps   1.928V     1.329V     1.894V
642.3ps   1.717V     1.329V     353.1mV
784.6ps   1.216V     1.321V     42.03mV
1.038ns   224.3mV    1.231V     10.53mV
1.187ns   41.6mV     1.095V     6.998mV
1.755ns   9.046mV    373.9mV    3.481mV
2.185ns   5.406mV    45.12mV    3.232mV
5.084ns   2.111mV    3.176mV    3.054mV
